VERSION 5.8 ;
BUSBITCHARS "[]" ;
DIVIDERCHAR "/" ;
UNITS
    DATABASE MICRONS 1000 ;
END UNITS

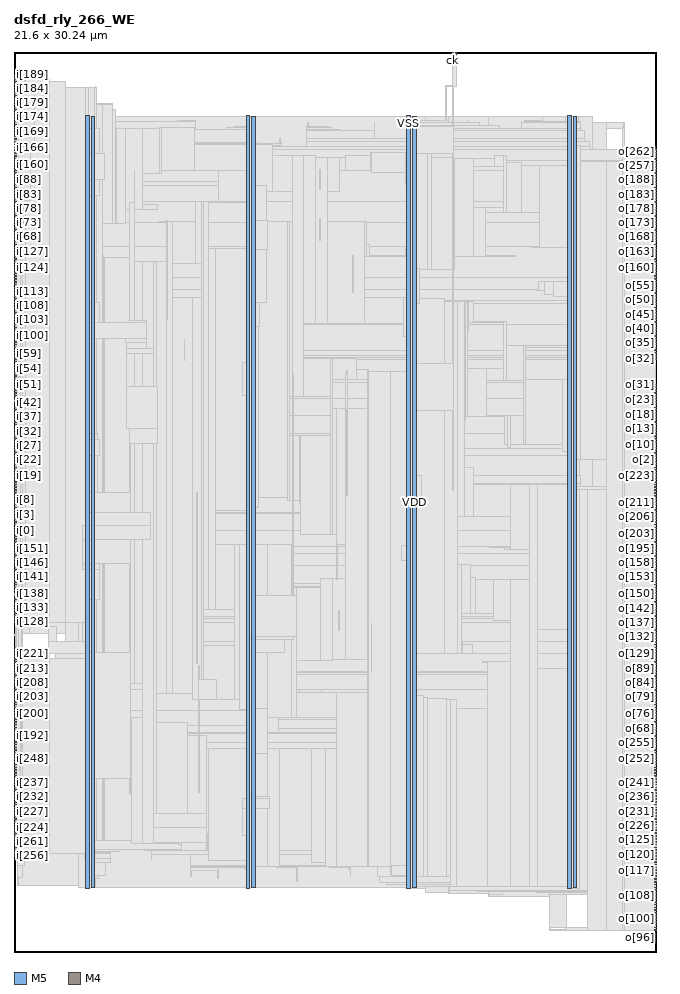
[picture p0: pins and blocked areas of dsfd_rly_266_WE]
MACRO dsfd_rly_266_WE
  FOREIGN dsfd_rly_266_WE 0 0 ;
  CLASS BLOCK ;
  SIZE 21.6 BY 30.24 ;
  PIN ck
    DIRECTION INPUT ;
    USE SIGNAL ;
    PORT
      LAYER M5 ;
        RECT  14.736 30.156 14.76 30.24 ;
    END
  END ck
  PIN i[0]
    DIRECTION INPUT ;
    USE SIGNAL ;
    PORT
      LAYER M4 ;
        RECT  0 14.16 0.084 14.184 ;
    END
  END i[0]
  PIN i[100]
    DIRECTION INPUT ;
    USE SIGNAL ;
    PORT
      LAYER M4 ;
        RECT  0 20.688 0.084 20.712 ;
    END
  END i[100]
  PIN i[101]
    DIRECTION INPUT ;
    USE SIGNAL ;
    PORT
      LAYER M4 ;
        RECT  0 20.784 0.084 20.808 ;
    END
  END i[101]
  PIN i[102]
    DIRECTION INPUT ;
    USE SIGNAL ;
    PORT
      LAYER M4 ;
        RECT  0 20.88 0.084 20.904 ;
    END
  END i[102]
  PIN i[103]
    DIRECTION INPUT ;
    USE SIGNAL ;
    PORT
      LAYER M4 ;
        RECT  0 20.976 0.084 21 ;
    END
  END i[103]
  PIN i[104]
    DIRECTION INPUT ;
    USE SIGNAL ;
    PORT
      LAYER M4 ;
        RECT  0 21.072 0.084 21.096 ;
    END
  END i[104]
  PIN i[105]
    DIRECTION INPUT ;
    USE SIGNAL ;
    PORT
      LAYER M4 ;
        RECT  0 21.168 0.084 21.192 ;
    END
  END i[105]
  PIN i[106]
    DIRECTION INPUT ;
    USE SIGNAL ;
    PORT
      LAYER M4 ;
        RECT  0 21.264 0.084 21.288 ;
    END
  END i[106]
  PIN i[107]
    DIRECTION INPUT ;
    USE SIGNAL ;
    PORT
      LAYER M4 ;
        RECT  0 21.36 0.084 21.384 ;
    END
  END i[107]
  PIN i[108]
    DIRECTION INPUT ;
    USE SIGNAL ;
    PORT
      LAYER M4 ;
        RECT  0 21.456 0.084 21.48 ;
    END
  END i[108]
  PIN i[109]
    DIRECTION INPUT ;
    USE SIGNAL ;
    PORT
      LAYER M4 ;
        RECT  0 21.552 0.084 21.576 ;
    END
  END i[109]
  PIN i[10]
    DIRECTION INPUT ;
    USE SIGNAL ;
    PORT
      LAYER M4 ;
        RECT  0 15.12 0.084 15.144 ;
    END
  END i[10]
  PIN i[110]
    DIRECTION INPUT ;
    USE SIGNAL ;
    PORT
      LAYER M4 ;
        RECT  0 21.648 0.084 21.672 ;
    END
  END i[110]
  PIN i[111]
    DIRECTION INPUT ;
    USE SIGNAL ;
    PORT
      LAYER M4 ;
        RECT  0 21.744 0.084 21.768 ;
    END
  END i[111]
  PIN i[112]
    DIRECTION INPUT ;
    USE SIGNAL ;
    PORT
      LAYER M4 ;
        RECT  0 21.84 0.084 21.864 ;
    END
  END i[112]
  PIN i[113]
    DIRECTION INPUT ;
    USE SIGNAL ;
    PORT
      LAYER M4 ;
        RECT  0 21.936 0.084 21.96 ;
    END
  END i[113]
  PIN i[114]
    DIRECTION INPUT ;
    USE SIGNAL ;
    PORT
      LAYER M4 ;
        RECT  0 22.032 0.084 22.056 ;
    END
  END i[114]
  PIN i[115]
    DIRECTION INPUT ;
    USE SIGNAL ;
    PORT
      LAYER M4 ;
        RECT  0 22.128 0.084 22.152 ;
    END
  END i[115]
  PIN i[116]
    DIRECTION INPUT ;
    USE SIGNAL ;
    PORT
      LAYER M4 ;
        RECT  0 22.224 0.084 22.248 ;
    END
  END i[116]
  PIN i[117]
    DIRECTION INPUT ;
    USE SIGNAL ;
    PORT
      LAYER M4 ;
        RECT  0 22.32 0.084 22.344 ;
    END
  END i[117]
  PIN i[118]
    DIRECTION INPUT ;
    USE SIGNAL ;
    PORT
      LAYER M4 ;
        RECT  0 22.416 0.084 22.44 ;
    END
  END i[118]
  PIN i[119]
    DIRECTION INPUT ;
    USE SIGNAL ;
    PORT
      LAYER M4 ;
        RECT  0 22.512 0.084 22.536 ;
    END
  END i[119]
  PIN i[11]
    DIRECTION INPUT ;
    USE SIGNAL ;
    PORT
      LAYER M4 ;
        RECT  0 15.216 0.084 15.24 ;
    END
  END i[11]
  PIN i[120]
    DIRECTION INPUT ;
    USE SIGNAL ;
    PORT
      LAYER M4 ;
        RECT  0 22.608 0.084 22.632 ;
    END
  END i[120]
  PIN i[121]
    DIRECTION INPUT ;
    USE SIGNAL ;
    PORT
      LAYER M4 ;
        RECT  0 22.704 0.084 22.728 ;
    END
  END i[121]
  PIN i[122]
    DIRECTION INPUT ;
    USE SIGNAL ;
    PORT
      LAYER M4 ;
        RECT  0 22.8 0.084 22.824 ;
    END
  END i[122]
  PIN i[123]
    DIRECTION INPUT ;
    USE SIGNAL ;
    PORT
      LAYER M4 ;
        RECT  0 22.896 0.084 22.92 ;
    END
  END i[123]
  PIN i[124]
    DIRECTION INPUT ;
    USE SIGNAL ;
    PORT
      LAYER M4 ;
        RECT  0 22.992 0.084 23.016 ;
    END
  END i[124]
  PIN i[125]
    DIRECTION INPUT ;
    USE SIGNAL ;
    PORT
      LAYER M4 ;
        RECT  0 23.088 0.084 23.112 ;
    END
  END i[125]
  PIN i[126]
    DIRECTION INPUT ;
    USE SIGNAL ;
    PORT
      LAYER M4 ;
        RECT  0 23.184 0.084 23.208 ;
    END
  END i[126]
  PIN i[127]
    DIRECTION INPUT ;
    USE SIGNAL ;
    PORT
      LAYER M4 ;
        RECT  0 23.28 0.084 23.304 ;
    END
  END i[127]
  PIN i[128]
    DIRECTION INPUT ;
    USE SIGNAL ;
    PORT
      LAYER M4 ;
        RECT  0 11.088 0.084 11.112 ;
    END
  END i[128]
  PIN i[129]
    DIRECTION INPUT ;
    USE SIGNAL ;
    PORT
      LAYER M4 ;
        RECT  0 11.184 0.084 11.208 ;
    END
  END i[129]
  PIN i[12]
    DIRECTION INPUT ;
    USE SIGNAL ;
    PORT
      LAYER M4 ;
        RECT  0 15.312 0.084 15.336 ;
    END
  END i[12]
  PIN i[130]
    DIRECTION INPUT ;
    USE SIGNAL ;
    PORT
      LAYER M4 ;
        RECT  0 11.28 0.084 11.304 ;
    END
  END i[130]
  PIN i[131]
    DIRECTION INPUT ;
    USE SIGNAL ;
    PORT
      LAYER M4 ;
        RECT  0 11.376 0.084 11.4 ;
    END
  END i[131]
  PIN i[132]
    DIRECTION INPUT ;
    USE SIGNAL ;
    PORT
      LAYER M4 ;
        RECT  0 11.472 0.084 11.496 ;
    END
  END i[132]
  PIN i[133]
    DIRECTION INPUT ;
    USE SIGNAL ;
    PORT
      LAYER M4 ;
        RECT  0 11.568 0.084 11.592 ;
    END
  END i[133]
  PIN i[134]
    DIRECTION INPUT ;
    USE SIGNAL ;
    PORT
      LAYER M4 ;
        RECT  0 11.664 0.084 11.688 ;
    END
  END i[134]
  PIN i[135]
    DIRECTION INPUT ;
    USE SIGNAL ;
    PORT
      LAYER M4 ;
        RECT  0 11.76 0.084 11.784 ;
    END
  END i[135]
  PIN i[136]
    DIRECTION INPUT ;
    USE SIGNAL ;
    PORT
      LAYER M4 ;
        RECT  0 11.856 0.084 11.88 ;
    END
  END i[136]
  PIN i[137]
    DIRECTION INPUT ;
    USE SIGNAL ;
    PORT
      LAYER M4 ;
        RECT  0 11.952 0.084 11.976 ;
    END
  END i[137]
  PIN i[138]
    DIRECTION INPUT ;
    USE SIGNAL ;
    PORT
      LAYER M4 ;
        RECT  0 12.048 0.084 12.072 ;
    END
  END i[138]
  PIN i[139]
    DIRECTION INPUT ;
    USE SIGNAL ;
    PORT
      LAYER M4 ;
        RECT  0 12.144 0.084 12.168 ;
    END
  END i[139]
  PIN i[13]
    DIRECTION INPUT ;
    USE SIGNAL ;
    PORT
      LAYER M4 ;
        RECT  0 15.408 0.084 15.432 ;
    END
  END i[13]
  PIN i[140]
    DIRECTION INPUT ;
    USE SIGNAL ;
    PORT
      LAYER M4 ;
        RECT  0 12.24 0.084 12.264 ;
    END
  END i[140]
  PIN i[141]
    DIRECTION INPUT ;
    USE SIGNAL ;
    PORT
      LAYER M4 ;
        RECT  0 12.336 0.084 12.36 ;
    END
  END i[141]
  PIN i[142]
    DIRECTION INPUT ;
    USE SIGNAL ;
    PORT
      LAYER M4 ;
        RECT  0 12.432 0.084 12.456 ;
    END
  END i[142]
  PIN i[143]
    DIRECTION INPUT ;
    USE SIGNAL ;
    PORT
      LAYER M4 ;
        RECT  0 12.528 0.084 12.552 ;
    END
  END i[143]
  PIN i[144]
    DIRECTION INPUT ;
    USE SIGNAL ;
    PORT
      LAYER M4 ;
        RECT  0 12.624 0.084 12.648 ;
    END
  END i[144]
  PIN i[145]
    DIRECTION INPUT ;
    USE SIGNAL ;
    PORT
      LAYER M4 ;
        RECT  0 12.72 0.084 12.744 ;
    END
  END i[145]
  PIN i[146]
    DIRECTION INPUT ;
    USE SIGNAL ;
    PORT
      LAYER M4 ;
        RECT  0 12.816 0.084 12.84 ;
    END
  END i[146]
  PIN i[147]
    DIRECTION INPUT ;
    USE SIGNAL ;
    PORT
      LAYER M4 ;
        RECT  0 12.912 0.084 12.936 ;
    END
  END i[147]
  PIN i[148]
    DIRECTION INPUT ;
    USE SIGNAL ;
    PORT
      LAYER M4 ;
        RECT  0 13.008 0.084 13.032 ;
    END
  END i[148]
  PIN i[149]
    DIRECTION INPUT ;
    USE SIGNAL ;
    PORT
      LAYER M4 ;
        RECT  0 13.104 0.084 13.128 ;
    END
  END i[149]
  PIN i[14]
    DIRECTION INPUT ;
    USE SIGNAL ;
    PORT
      LAYER M4 ;
        RECT  0 15.504 0.084 15.528 ;
    END
  END i[14]
  PIN i[150]
    DIRECTION INPUT ;
    USE SIGNAL ;
    PORT
      LAYER M4 ;
        RECT  0 13.2 0.084 13.224 ;
    END
  END i[150]
  PIN i[151]
    DIRECTION INPUT ;
    USE SIGNAL ;
    PORT
      LAYER M4 ;
        RECT  0 13.296 0.084 13.32 ;
    END
  END i[151]
  PIN i[152]
    DIRECTION INPUT ;
    USE SIGNAL ;
    PORT
      LAYER M4 ;
        RECT  0 13.392 0.084 13.416 ;
    END
  END i[152]
  PIN i[153]
    DIRECTION INPUT ;
    USE SIGNAL ;
    PORT
      LAYER M4 ;
        RECT  0 13.488 0.084 13.512 ;
    END
  END i[153]
  PIN i[154]
    DIRECTION INPUT ;
    USE SIGNAL ;
    PORT
      LAYER M4 ;
        RECT  0 13.584 0.084 13.608 ;
    END
  END i[154]
  PIN i[155]
    DIRECTION INPUT ;
    USE SIGNAL ;
    PORT
      LAYER M4 ;
        RECT  0 13.68 0.084 13.704 ;
    END
  END i[155]
  PIN i[156]
    DIRECTION INPUT ;
    USE SIGNAL ;
    PORT
      LAYER M4 ;
        RECT  0 13.776 0.084 13.8 ;
    END
  END i[156]
  PIN i[157]
    DIRECTION INPUT ;
    USE SIGNAL ;
    PORT
      LAYER M4 ;
        RECT  0 13.872 0.084 13.896 ;
    END
  END i[157]
  PIN i[158]
    DIRECTION INPUT ;
    USE SIGNAL ;
    PORT
      LAYER M4 ;
        RECT  0 13.968 0.084 13.992 ;
    END
  END i[158]
  PIN i[159]
    DIRECTION INPUT ;
    USE SIGNAL ;
    PORT
      LAYER M4 ;
        RECT  0 14.064 0.084 14.088 ;
    END
  END i[159]
  PIN i[15]
    DIRECTION INPUT ;
    USE SIGNAL ;
    PORT
      LAYER M4 ;
        RECT  0 15.6 0.084 15.624 ;
    END
  END i[15]
  PIN i[160]
    DIRECTION INPUT ;
    USE SIGNAL ;
    PORT
      LAYER M4 ;
        RECT  0 26.448 0.084 26.472 ;
    END
  END i[160]
  PIN i[161]
    DIRECTION INPUT ;
    USE SIGNAL ;
    PORT
      LAYER M4 ;
        RECT  0 26.544 0.084 26.568 ;
    END
  END i[161]
  PIN i[162]
    DIRECTION INPUT ;
    USE SIGNAL ;
    PORT
      LAYER M4 ;
        RECT  0 26.64 0.084 26.664 ;
    END
  END i[162]
  PIN i[163]
    DIRECTION INPUT ;
    USE SIGNAL ;
    PORT
      LAYER M4 ;
        RECT  0 26.736 0.084 26.76 ;
    END
  END i[163]
  PIN i[164]
    DIRECTION INPUT ;
    USE SIGNAL ;
    PORT
      LAYER M4 ;
        RECT  0 26.832 0.084 26.856 ;
    END
  END i[164]
  PIN i[165]
    DIRECTION INPUT ;
    USE SIGNAL ;
    PORT
      LAYER M4 ;
        RECT  0 26.928 0.084 26.952 ;
    END
  END i[165]
  PIN i[166]
    DIRECTION INPUT ;
    USE SIGNAL ;
    PORT
      LAYER M4 ;
        RECT  0 27.024 0.084 27.048 ;
    END
  END i[166]
  PIN i[167]
    DIRECTION INPUT ;
    USE SIGNAL ;
    PORT
      LAYER M4 ;
        RECT  0 27.12 0.084 27.144 ;
    END
  END i[167]
  PIN i[168]
    DIRECTION INPUT ;
    USE SIGNAL ;
    PORT
      LAYER M4 ;
        RECT  0 27.216 0.084 27.24 ;
    END
  END i[168]
  PIN i[169]
    DIRECTION INPUT ;
    USE SIGNAL ;
    PORT
      LAYER M4 ;
        RECT  0 27.312 0.084 27.336 ;
    END
  END i[169]
  PIN i[16]
    DIRECTION INPUT ;
    USE SIGNAL ;
    PORT
      LAYER M4 ;
        RECT  0 15.696 0.084 15.72 ;
    END
  END i[16]
  PIN i[170]
    DIRECTION INPUT ;
    USE SIGNAL ;
    PORT
      LAYER M4 ;
        RECT  0 27.408 0.084 27.432 ;
    END
  END i[170]
  PIN i[171]
    DIRECTION INPUT ;
    USE SIGNAL ;
    PORT
      LAYER M4 ;
        RECT  0 27.504 0.084 27.528 ;
    END
  END i[171]
  PIN i[172]
    DIRECTION INPUT ;
    USE SIGNAL ;
    PORT
      LAYER M4 ;
        RECT  0 27.6 0.084 27.624 ;
    END
  END i[172]
  PIN i[173]
    DIRECTION INPUT ;
    USE SIGNAL ;
    PORT
      LAYER M4 ;
        RECT  0 27.696 0.084 27.72 ;
    END
  END i[173]
  PIN i[174]
    DIRECTION INPUT ;
    USE SIGNAL ;
    PORT
      LAYER M4 ;
        RECT  0 27.792 0.084 27.816 ;
    END
  END i[174]
  PIN i[175]
    DIRECTION INPUT ;
    USE SIGNAL ;
    PORT
      LAYER M4 ;
        RECT  0 27.888 0.084 27.912 ;
    END
  END i[175]
  PIN i[176]
    DIRECTION INPUT ;
    USE SIGNAL ;
    PORT
      LAYER M4 ;
        RECT  0 27.984 0.084 28.008 ;
    END
  END i[176]
  PIN i[177]
    DIRECTION INPUT ;
    USE SIGNAL ;
    PORT
      LAYER M4 ;
        RECT  0 28.08 0.084 28.104 ;
    END
  END i[177]
  PIN i[178]
    DIRECTION INPUT ;
    USE SIGNAL ;
    PORT
      LAYER M4 ;
        RECT  0 28.176 0.084 28.2 ;
    END
  END i[178]
  PIN i[179]
    DIRECTION INPUT ;
    USE SIGNAL ;
    PORT
      LAYER M4 ;
        RECT  0 28.272 0.084 28.296 ;
    END
  END i[179]
  PIN i[17]
    DIRECTION INPUT ;
    USE SIGNAL ;
    PORT
      LAYER M4 ;
        RECT  0 15.792 0.084 15.816 ;
    END
  END i[17]
  PIN i[180]
    DIRECTION INPUT ;
    USE SIGNAL ;
    PORT
      LAYER M4 ;
        RECT  0 28.368 0.084 28.392 ;
    END
  END i[180]
  PIN i[181]
    DIRECTION INPUT ;
    USE SIGNAL ;
    PORT
      LAYER M4 ;
        RECT  0 28.464 0.084 28.488 ;
    END
  END i[181]
  PIN i[182]
    DIRECTION INPUT ;
    USE SIGNAL ;
    PORT
      LAYER M4 ;
        RECT  0 28.56 0.084 28.584 ;
    END
  END i[182]
  PIN i[183]
    DIRECTION INPUT ;
    USE SIGNAL ;
    PORT
      LAYER M4 ;
        RECT  0 28.656 0.084 28.68 ;
    END
  END i[183]
  PIN i[184]
    DIRECTION INPUT ;
    USE SIGNAL ;
    PORT
      LAYER M4 ;
        RECT  0 28.752 0.084 28.776 ;
    END
  END i[184]
  PIN i[185]
    DIRECTION INPUT ;
    USE SIGNAL ;
    PORT
      LAYER M4 ;
        RECT  0 28.848 0.084 28.872 ;
    END
  END i[185]
  PIN i[186]
    DIRECTION INPUT ;
    USE SIGNAL ;
    PORT
      LAYER M4 ;
        RECT  0 28.944 0.084 28.968 ;
    END
  END i[186]
  PIN i[187]
    DIRECTION INPUT ;
    USE SIGNAL ;
    PORT
      LAYER M4 ;
        RECT  0 29.04 0.084 29.064 ;
    END
  END i[187]
  PIN i[188]
    DIRECTION INPUT ;
    USE SIGNAL ;
    PORT
      LAYER M4 ;
        RECT  0 29.136 0.084 29.16 ;
    END
  END i[188]
  PIN i[189]
    DIRECTION INPUT ;
    USE SIGNAL ;
    PORT
      LAYER M4 ;
        RECT  0 29.232 0.084 29.256 ;
    END
  END i[189]
  PIN i[18]
    DIRECTION INPUT ;
    USE SIGNAL ;
    PORT
      LAYER M4 ;
        RECT  0 15.888 0.084 15.912 ;
    END
  END i[18]
  PIN i[190]
    DIRECTION INPUT ;
    USE SIGNAL ;
    PORT
      LAYER M4 ;
        RECT  0 29.328 0.084 29.352 ;
    END
  END i[190]
  PIN i[191]
    DIRECTION INPUT ;
    USE SIGNAL ;
    PORT
      LAYER M4 ;
        RECT  0 29.424 0.084 29.448 ;
    END
  END i[191]
  PIN i[192]
    DIRECTION INPUT ;
    USE SIGNAL ;
    PORT
      LAYER M4 ;
        RECT  0 7.248 0.084 7.272 ;
    END
  END i[192]
  PIN i[193]
    DIRECTION INPUT ;
    USE SIGNAL ;
    PORT
      LAYER M4 ;
        RECT  0 7.344 0.084 7.368 ;
    END
  END i[193]
  PIN i[194]
    DIRECTION INPUT ;
    USE SIGNAL ;
    PORT
      LAYER M4 ;
        RECT  0 7.44 0.084 7.464 ;
    END
  END i[194]
  PIN i[195]
    DIRECTION INPUT ;
    USE SIGNAL ;
    PORT
      LAYER M4 ;
        RECT  0 7.536 0.084 7.56 ;
    END
  END i[195]
  PIN i[196]
    DIRECTION INPUT ;
    USE SIGNAL ;
    PORT
      LAYER M4 ;
        RECT  0 7.632 0.084 7.656 ;
    END
  END i[196]
  PIN i[197]
    DIRECTION INPUT ;
    USE SIGNAL ;
    PORT
      LAYER M4 ;
        RECT  0 7.728 0.084 7.752 ;
    END
  END i[197]
  PIN i[198]
    DIRECTION INPUT ;
    USE SIGNAL ;
    PORT
      LAYER M4 ;
        RECT  0 7.824 0.084 7.848 ;
    END
  END i[198]
  PIN i[199]
    DIRECTION INPUT ;
    USE SIGNAL ;
    PORT
      LAYER M4 ;
        RECT  0 7.92 0.084 7.944 ;
    END
  END i[199]
  PIN i[19]
    DIRECTION INPUT ;
    USE SIGNAL ;
    PORT
      LAYER M4 ;
        RECT  0 15.984 0.084 16.008 ;
    END
  END i[19]
  PIN i[1]
    DIRECTION INPUT ;
    USE SIGNAL ;
    PORT
      LAYER M4 ;
        RECT  0 14.256 0.084 14.28 ;
    END
  END i[1]
  PIN i[200]
    DIRECTION INPUT ;
    USE SIGNAL ;
    PORT
      LAYER M4 ;
        RECT  0 8.016 0.084 8.04 ;
    END
  END i[200]
  PIN i[201]
    DIRECTION INPUT ;
    USE SIGNAL ;
    PORT
      LAYER M4 ;
        RECT  0 8.112 0.084 8.136 ;
    END
  END i[201]
  PIN i[202]
    DIRECTION INPUT ;
    USE SIGNAL ;
    PORT
      LAYER M4 ;
        RECT  0 8.208 0.084 8.232 ;
    END
  END i[202]
  PIN i[203]
    DIRECTION INPUT ;
    USE SIGNAL ;
    PORT
      LAYER M4 ;
        RECT  0 8.304 0.084 8.328 ;
    END
  END i[203]
  PIN i[204]
    DIRECTION INPUT ;
    USE SIGNAL ;
    PORT
      LAYER M4 ;
        RECT  0 8.4 0.084 8.424 ;
    END
  END i[204]
  PIN i[205]
    DIRECTION INPUT ;
    USE SIGNAL ;
    PORT
      LAYER M4 ;
        RECT  0 8.496 0.084 8.52 ;
    END
  END i[205]
  PIN i[206]
    DIRECTION INPUT ;
    USE SIGNAL ;
    PORT
      LAYER M4 ;
        RECT  0 8.592 0.084 8.616 ;
    END
  END i[206]
  PIN i[207]
    DIRECTION INPUT ;
    USE SIGNAL ;
    PORT
      LAYER M4 ;
        RECT  0 8.688 0.084 8.712 ;
    END
  END i[207]
  PIN i[208]
    DIRECTION INPUT ;
    USE SIGNAL ;
    PORT
      LAYER M4 ;
        RECT  0 8.784 0.084 8.808 ;
    END
  END i[208]
  PIN i[209]
    DIRECTION INPUT ;
    USE SIGNAL ;
    PORT
      LAYER M4 ;
        RECT  0 8.88 0.084 8.904 ;
    END
  END i[209]
  PIN i[20]
    DIRECTION INPUT ;
    USE SIGNAL ;
    PORT
      LAYER M4 ;
        RECT  0 16.08 0.084 16.104 ;
    END
  END i[20]
  PIN i[210]
    DIRECTION INPUT ;
    USE SIGNAL ;
    PORT
      LAYER M4 ;
        RECT  0 8.976 0.084 9 ;
    END
  END i[210]
  PIN i[211]
    DIRECTION INPUT ;
    USE SIGNAL ;
    PORT
      LAYER M4 ;
        RECT  0 9.072 0.084 9.096 ;
    END
  END i[211]
  PIN i[212]
    DIRECTION INPUT ;
    USE SIGNAL ;
    PORT
      LAYER M4 ;
        RECT  0 9.168 0.084 9.192 ;
    END
  END i[212]
  PIN i[213]
    DIRECTION INPUT ;
    USE SIGNAL ;
    PORT
      LAYER M4 ;
        RECT  0 9.264 0.084 9.288 ;
    END
  END i[213]
  PIN i[214]
    DIRECTION INPUT ;
    USE SIGNAL ;
    PORT
      LAYER M4 ;
        RECT  0 9.36 0.084 9.384 ;
    END
  END i[214]
  PIN i[215]
    DIRECTION INPUT ;
    USE SIGNAL ;
    PORT
      LAYER M4 ;
        RECT  0 9.456 0.084 9.48 ;
    END
  END i[215]
  PIN i[216]
    DIRECTION INPUT ;
    USE SIGNAL ;
    PORT
      LAYER M4 ;
        RECT  0 9.552 0.084 9.576 ;
    END
  END i[216]
  PIN i[217]
    DIRECTION INPUT ;
    USE SIGNAL ;
    PORT
      LAYER M4 ;
        RECT  0 9.648 0.084 9.672 ;
    END
  END i[217]
  PIN i[218]
    DIRECTION INPUT ;
    USE SIGNAL ;
    PORT
      LAYER M4 ;
        RECT  0 9.744 0.084 9.768 ;
    END
  END i[218]
  PIN i[219]
    DIRECTION INPUT ;
    USE SIGNAL ;
    PORT
      LAYER M4 ;
        RECT  0 9.84 0.084 9.864 ;
    END
  END i[219]
  PIN i[21]
    DIRECTION INPUT ;
    USE SIGNAL ;
    PORT
      LAYER M4 ;
        RECT  0 16.176 0.084 16.2 ;
    END
  END i[21]
  PIN i[220]
    DIRECTION INPUT ;
    USE SIGNAL ;
    PORT
      LAYER M4 ;
        RECT  0 9.936 0.084 9.96 ;
    END
  END i[220]
  PIN i[221]
    DIRECTION INPUT ;
    USE SIGNAL ;
    PORT
      LAYER M4 ;
        RECT  0 10.032 0.084 10.056 ;
    END
  END i[221]
  PIN i[222]
    DIRECTION INPUT ;
    USE SIGNAL ;
    PORT
      LAYER M4 ;
        RECT  0 10.128 0.084 10.152 ;
    END
  END i[222]
  PIN i[223]
    DIRECTION INPUT ;
    USE SIGNAL ;
    PORT
      LAYER M4 ;
        RECT  0 10.224 0.084 10.248 ;
    END
  END i[223]
  PIN i[224]
    DIRECTION INPUT ;
    USE SIGNAL ;
    PORT
      LAYER M4 ;
        RECT  0 4.176 0.084 4.2 ;
    END
  END i[224]
  PIN i[225]
    DIRECTION INPUT ;
    USE SIGNAL ;
    PORT
      LAYER M4 ;
        RECT  0 4.272 0.084 4.296 ;
    END
  END i[225]
  PIN i[226]
    DIRECTION INPUT ;
    USE SIGNAL ;
    PORT
      LAYER M4 ;
        RECT  0 4.368 0.084 4.392 ;
    END
  END i[226]
  PIN i[227]
    DIRECTION INPUT ;
    USE SIGNAL ;
    PORT
      LAYER M4 ;
        RECT  0 4.464 0.084 4.488 ;
    END
  END i[227]
  PIN i[228]
    DIRECTION INPUT ;
    USE SIGNAL ;
    PORT
      LAYER M4 ;
        RECT  0 4.56 0.084 4.584 ;
    END
  END i[228]
  PIN i[229]
    DIRECTION INPUT ;
    USE SIGNAL ;
    PORT
      LAYER M4 ;
        RECT  0 4.656 0.084 4.68 ;
    END
  END i[229]
  PIN i[22]
    DIRECTION INPUT ;
    USE SIGNAL ;
    PORT
      LAYER M4 ;
        RECT  0 16.272 0.084 16.296 ;
    END
  END i[22]
  PIN i[230]
    DIRECTION INPUT ;
    USE SIGNAL ;
    PORT
      LAYER M4 ;
        RECT  0 4.752 0.084 4.776 ;
    END
  END i[230]
  PIN i[231]
    DIRECTION INPUT ;
    USE SIGNAL ;
    PORT
      LAYER M4 ;
        RECT  0 4.848 0.084 4.872 ;
    END
  END i[231]
  PIN i[232]
    DIRECTION INPUT ;
    USE SIGNAL ;
    PORT
      LAYER M4 ;
        RECT  0 4.944 0.084 4.968 ;
    END
  END i[232]
  PIN i[233]
    DIRECTION INPUT ;
    USE SIGNAL ;
    PORT
      LAYER M4 ;
        RECT  0 5.04 0.084 5.064 ;
    END
  END i[233]
  PIN i[234]
    DIRECTION INPUT ;
    USE SIGNAL ;
    PORT
      LAYER M4 ;
        RECT  0 5.136 0.084 5.16 ;
    END
  END i[234]
  PIN i[235]
    DIRECTION INPUT ;
    USE SIGNAL ;
    PORT
      LAYER M4 ;
        RECT  0 5.232 0.084 5.256 ;
    END
  END i[235]
  PIN i[236]
    DIRECTION INPUT ;
    USE SIGNAL ;
    PORT
      LAYER M4 ;
        RECT  0 5.328 0.084 5.352 ;
    END
  END i[236]
  PIN i[237]
    DIRECTION INPUT ;
    USE SIGNAL ;
    PORT
      LAYER M4 ;
        RECT  0 5.424 0.084 5.448 ;
    END
  END i[237]
  PIN i[238]
    DIRECTION INPUT ;
    USE SIGNAL ;
    PORT
      LAYER M4 ;
        RECT  0 5.52 0.084 5.544 ;
    END
  END i[238]
  PIN i[239]
    DIRECTION INPUT ;
    USE SIGNAL ;
    PORT
      LAYER M4 ;
        RECT  0 5.616 0.084 5.64 ;
    END
  END i[239]
  PIN i[23]
    DIRECTION INPUT ;
    USE SIGNAL ;
    PORT
      LAYER M4 ;
        RECT  0 16.368 0.084 16.392 ;
    END
  END i[23]
  PIN i[240]
    DIRECTION INPUT ;
    USE SIGNAL ;
    PORT
      LAYER M4 ;
        RECT  0 5.712 0.084 5.736 ;
    END
  END i[240]
  PIN i[241]
    DIRECTION INPUT ;
    USE SIGNAL ;
    PORT
      LAYER M4 ;
        RECT  0 5.808 0.084 5.832 ;
    END
  END i[241]
  PIN i[242]
    DIRECTION INPUT ;
    USE SIGNAL ;
    PORT
      LAYER M4 ;
        RECT  0 5.904 0.084 5.928 ;
    END
  END i[242]
  PIN i[243]
    DIRECTION INPUT ;
    USE SIGNAL ;
    PORT
      LAYER M4 ;
        RECT  0 6 0.084 6.024 ;
    END
  END i[243]
  PIN i[244]
    DIRECTION INPUT ;
    USE SIGNAL ;
    PORT
      LAYER M4 ;
        RECT  0 6.096 0.084 6.12 ;
    END
  END i[244]
  PIN i[245]
    DIRECTION INPUT ;
    USE SIGNAL ;
    PORT
      LAYER M4 ;
        RECT  0 6.192 0.084 6.216 ;
    END
  END i[245]
  PIN i[246]
    DIRECTION INPUT ;
    USE SIGNAL ;
    PORT
      LAYER M4 ;
        RECT  0 6.288 0.084 6.312 ;
    END
  END i[246]
  PIN i[247]
    DIRECTION INPUT ;
    USE SIGNAL ;
    PORT
      LAYER M4 ;
        RECT  0 6.384 0.084 6.408 ;
    END
  END i[247]
  PIN i[248]
    DIRECTION INPUT ;
    USE SIGNAL ;
    PORT
      LAYER M4 ;
        RECT  0 6.48 0.084 6.504 ;
    END
  END i[248]
  PIN i[249]
    DIRECTION INPUT ;
    USE SIGNAL ;
    PORT
      LAYER M4 ;
        RECT  0 6.576 0.084 6.6 ;
    END
  END i[249]
  PIN i[24]
    DIRECTION INPUT ;
    USE SIGNAL ;
    PORT
      LAYER M4 ;
        RECT  0 16.464 0.084 16.488 ;
    END
  END i[24]
  PIN i[250]
    DIRECTION INPUT ;
    USE SIGNAL ;
    PORT
      LAYER M4 ;
        RECT  0 6.672 0.084 6.696 ;
    END
  END i[250]
  PIN i[251]
    DIRECTION INPUT ;
    USE SIGNAL ;
    PORT
      LAYER M4 ;
        RECT  0 6.768 0.084 6.792 ;
    END
  END i[251]
  PIN i[252]
    DIRECTION INPUT ;
    USE SIGNAL ;
    PORT
      LAYER M4 ;
        RECT  0 6.864 0.084 6.888 ;
    END
  END i[252]
  PIN i[253]
    DIRECTION INPUT ;
    USE SIGNAL ;
    PORT
      LAYER M4 ;
        RECT  0 6.96 0.084 6.984 ;
    END
  END i[253]
  PIN i[254]
    DIRECTION INPUT ;
    USE SIGNAL ;
    PORT
      LAYER M4 ;
        RECT  0 7.056 0.084 7.08 ;
    END
  END i[254]
  PIN i[255]
    DIRECTION INPUT ;
    USE SIGNAL ;
    PORT
      LAYER M4 ;
        RECT  0 7.152 0.084 7.176 ;
    END
  END i[255]
  PIN i[256]
    DIRECTION INPUT ;
    USE SIGNAL ;
    PORT
      LAYER M4 ;
        RECT  0 3.216 0.084 3.24 ;
    END
  END i[256]
  PIN i[257]
    DIRECTION INPUT ;
    USE SIGNAL ;
    PORT
      LAYER M4 ;
        RECT  0 3.312 0.084 3.336 ;
    END
  END i[257]
  PIN i[258]
    DIRECTION INPUT ;
    USE SIGNAL ;
    PORT
      LAYER M4 ;
        RECT  0 3.408 0.084 3.432 ;
    END
  END i[258]
  PIN i[259]
    DIRECTION INPUT ;
    USE SIGNAL ;
    PORT
      LAYER M4 ;
        RECT  0 3.504 0.084 3.528 ;
    END
  END i[259]
  PIN i[25]
    DIRECTION INPUT ;
    USE SIGNAL ;
    PORT
      LAYER M4 ;
        RECT  0 16.56 0.084 16.584 ;
    END
  END i[25]
  PIN i[260]
    DIRECTION INPUT ;
    USE SIGNAL ;
    PORT
      LAYER M4 ;
        RECT  0 3.6 0.084 3.624 ;
    END
  END i[260]
  PIN i[261]
    DIRECTION INPUT ;
    USE SIGNAL ;
    PORT
      LAYER M4 ;
        RECT  0 3.696 0.084 3.72 ;
    END
  END i[261]
  PIN i[262]
    DIRECTION INPUT ;
    USE SIGNAL ;
    PORT
      LAYER M4 ;
        RECT  0 3.792 0.084 3.816 ;
    END
  END i[262]
  PIN i[263]
    DIRECTION INPUT ;
    USE SIGNAL ;
    PORT
      LAYER M4 ;
        RECT  0 3.888 0.084 3.912 ;
    END
  END i[263]
  PIN i[264]
    DIRECTION INPUT ;
    USE SIGNAL ;
    PORT
      LAYER M4 ;
        RECT  0 3.984 0.084 4.008 ;
    END
  END i[264]
  PIN i[265]
    DIRECTION INPUT ;
    USE SIGNAL ;
    PORT
      LAYER M4 ;
        RECT  0 4.08 0.084 4.104 ;
    END
  END i[265]
  PIN i[26]
    DIRECTION INPUT ;
    USE SIGNAL ;
    PORT
      LAYER M4 ;
        RECT  0 16.656 0.084 16.68 ;
    END
  END i[26]
  PIN i[27]
    DIRECTION INPUT ;
    USE SIGNAL ;
    PORT
      LAYER M4 ;
        RECT  0 16.752 0.084 16.776 ;
    END
  END i[27]
  PIN i[28]
    DIRECTION INPUT ;
    USE SIGNAL ;
    PORT
      LAYER M4 ;
        RECT  0 16.848 0.084 16.872 ;
    END
  END i[28]
  PIN i[29]
    DIRECTION INPUT ;
    USE SIGNAL ;
    PORT
      LAYER M4 ;
        RECT  0 16.944 0.084 16.968 ;
    END
  END i[29]
  PIN i[2]
    DIRECTION INPUT ;
    USE SIGNAL ;
    PORT
      LAYER M4 ;
        RECT  0 14.352 0.084 14.376 ;
    END
  END i[2]
  PIN i[30]
    DIRECTION INPUT ;
    USE SIGNAL ;
    PORT
      LAYER M4 ;
        RECT  0 17.04 0.084 17.064 ;
    END
  END i[30]
  PIN i[31]
    DIRECTION INPUT ;
    USE SIGNAL ;
    PORT
      LAYER M4 ;
        RECT  0 17.136 0.084 17.16 ;
    END
  END i[31]
  PIN i[32]
    DIRECTION INPUT ;
    USE SIGNAL ;
    PORT
      LAYER M4 ;
        RECT  0 17.232 0.084 17.256 ;
    END
  END i[32]
  PIN i[33]
    DIRECTION INPUT ;
    USE SIGNAL ;
    PORT
      LAYER M4 ;
        RECT  0 17.328 0.084 17.352 ;
    END
  END i[33]
  PIN i[34]
    DIRECTION INPUT ;
    USE SIGNAL ;
    PORT
      LAYER M4 ;
        RECT  0 17.424 0.084 17.448 ;
    END
  END i[34]
  PIN i[35]
    DIRECTION INPUT ;
    USE SIGNAL ;
    PORT
      LAYER M4 ;
        RECT  0 17.52 0.084 17.544 ;
    END
  END i[35]
  PIN i[36]
    DIRECTION INPUT ;
    USE SIGNAL ;
    PORT
      LAYER M4 ;
        RECT  0 17.616 0.084 17.64 ;
    END
  END i[36]
  PIN i[37]
    DIRECTION INPUT ;
    USE SIGNAL ;
    PORT
      LAYER M4 ;
        RECT  0 17.712 0.084 17.736 ;
    END
  END i[37]
  PIN i[38]
    DIRECTION INPUT ;
    USE SIGNAL ;
    PORT
      LAYER M4 ;
        RECT  0 17.808 0.084 17.832 ;
    END
  END i[38]
  PIN i[39]
    DIRECTION INPUT ;
    USE SIGNAL ;
    PORT
      LAYER M4 ;
        RECT  0 17.904 0.084 17.928 ;
    END
  END i[39]
  PIN i[3]
    DIRECTION INPUT ;
    USE SIGNAL ;
    PORT
      LAYER M4 ;
        RECT  0 14.448 0.084 14.472 ;
    END
  END i[3]
  PIN i[40]
    DIRECTION INPUT ;
    USE SIGNAL ;
    PORT
      LAYER M4 ;
        RECT  0 18 0.084 18.024 ;
    END
  END i[40]
  PIN i[41]
    DIRECTION INPUT ;
    USE SIGNAL ;
    PORT
      LAYER M4 ;
        RECT  0 18.096 0.084 18.12 ;
    END
  END i[41]
  PIN i[42]
    DIRECTION INPUT ;
    USE SIGNAL ;
    PORT
      LAYER M4 ;
        RECT  0 18.192 0.084 18.216 ;
    END
  END i[42]
  PIN i[43]
    DIRECTION INPUT ;
    USE SIGNAL ;
    PORT
      LAYER M4 ;
        RECT  0 18.288 0.084 18.312 ;
    END
  END i[43]
  PIN i[44]
    DIRECTION INPUT ;
    USE SIGNAL ;
    PORT
      LAYER M4 ;
        RECT  0 18.384 0.084 18.408 ;
    END
  END i[44]
  PIN i[45]
    DIRECTION INPUT ;
    USE SIGNAL ;
    PORT
      LAYER M4 ;
        RECT  0 18.48 0.084 18.504 ;
    END
  END i[45]
  PIN i[46]
    DIRECTION INPUT ;
    USE SIGNAL ;
    PORT
      LAYER M4 ;
        RECT  0 18.576 0.084 18.6 ;
    END
  END i[46]
  PIN i[47]
    DIRECTION INPUT ;
    USE SIGNAL ;
    PORT
      LAYER M4 ;
        RECT  0 18.672 0.084 18.696 ;
    END
  END i[47]
  PIN i[48]
    DIRECTION INPUT ;
    USE SIGNAL ;
    PORT
      LAYER M4 ;
        RECT  0 18.768 0.084 18.792 ;
    END
  END i[48]
  PIN i[49]
    DIRECTION INPUT ;
    USE SIGNAL ;
    PORT
      LAYER M4 ;
        RECT  0 18.864 0.084 18.888 ;
    END
  END i[49]
  PIN i[4]
    DIRECTION INPUT ;
    USE SIGNAL ;
    PORT
      LAYER M4 ;
        RECT  0 14.544 0.084 14.568 ;
    END
  END i[4]
  PIN i[50]
    DIRECTION INPUT ;
    USE SIGNAL ;
    PORT
      LAYER M4 ;
        RECT  0 18.96 0.084 18.984 ;
    END
  END i[50]
  PIN i[51]
    DIRECTION INPUT ;
    USE SIGNAL ;
    PORT
      LAYER M4 ;
        RECT  0 19.056 0.084 19.08 ;
    END
  END i[51]
  PIN i[52]
    DIRECTION INPUT ;
    USE SIGNAL ;
    PORT
      LAYER M4 ;
        RECT  0 19.152 0.084 19.176 ;
    END
  END i[52]
  PIN i[53]
    DIRECTION INPUT ;
    USE SIGNAL ;
    PORT
      LAYER M4 ;
        RECT  0 19.248 0.084 19.272 ;
    END
  END i[53]
  PIN i[54]
    DIRECTION INPUT ;
    USE SIGNAL ;
    PORT
      LAYER M4 ;
        RECT  0 19.344 0.084 19.368 ;
    END
  END i[54]
  PIN i[55]
    DIRECTION INPUT ;
    USE SIGNAL ;
    PORT
      LAYER M4 ;
        RECT  0 19.44 0.084 19.464 ;
    END
  END i[55]
  PIN i[56]
    DIRECTION INPUT ;
    USE SIGNAL ;
    PORT
      LAYER M4 ;
        RECT  0 19.536 0.084 19.56 ;
    END
  END i[56]
  PIN i[57]
    DIRECTION INPUT ;
    USE SIGNAL ;
    PORT
      LAYER M4 ;
        RECT  0 19.632 0.084 19.656 ;
    END
  END i[57]
  PIN i[58]
    DIRECTION INPUT ;
    USE SIGNAL ;
    PORT
      LAYER M4 ;
        RECT  0 19.728 0.084 19.752 ;
    END
  END i[58]
  PIN i[59]
    DIRECTION INPUT ;
    USE SIGNAL ;
    PORT
      LAYER M4 ;
        RECT  0 19.824 0.084 19.848 ;
    END
  END i[59]
  PIN i[5]
    DIRECTION INPUT ;
    USE SIGNAL ;
    PORT
      LAYER M4 ;
        RECT  0 14.64 0.084 14.664 ;
    END
  END i[5]
  PIN i[60]
    DIRECTION INPUT ;
    USE SIGNAL ;
    PORT
      LAYER M4 ;
        RECT  0 19.92 0.084 19.944 ;
    END
  END i[60]
  PIN i[61]
    DIRECTION INPUT ;
    USE SIGNAL ;
    PORT
      LAYER M4 ;
        RECT  0 20.016 0.084 20.04 ;
    END
  END i[61]
  PIN i[62]
    DIRECTION INPUT ;
    USE SIGNAL ;
    PORT
      LAYER M4 ;
        RECT  0 20.112 0.084 20.136 ;
    END
  END i[62]
  PIN i[63]
    DIRECTION INPUT ;
    USE SIGNAL ;
    PORT
      LAYER M4 ;
        RECT  0 20.208 0.084 20.232 ;
    END
  END i[63]
  PIN i[64]
    DIRECTION INPUT ;
    USE SIGNAL ;
    PORT
      LAYER M4 ;
        RECT  0 23.376 0.084 23.4 ;
    END
  END i[64]
  PIN i[65]
    DIRECTION INPUT ;
    USE SIGNAL ;
    PORT
      LAYER M4 ;
        RECT  0 23.472 0.084 23.496 ;
    END
  END i[65]
  PIN i[66]
    DIRECTION INPUT ;
    USE SIGNAL ;
    PORT
      LAYER M4 ;
        RECT  0 23.568 0.084 23.592 ;
    END
  END i[66]
  PIN i[67]
    DIRECTION INPUT ;
    USE SIGNAL ;
    PORT
      LAYER M4 ;
        RECT  0 23.664 0.084 23.688 ;
    END
  END i[67]
  PIN i[68]
    DIRECTION INPUT ;
    USE SIGNAL ;
    PORT
      LAYER M4 ;
        RECT  0 23.76 0.084 23.784 ;
    END
  END i[68]
  PIN i[69]
    DIRECTION INPUT ;
    USE SIGNAL ;
    PORT
      LAYER M4 ;
        RECT  0 23.856 0.084 23.88 ;
    END
  END i[69]
  PIN i[6]
    DIRECTION INPUT ;
    USE SIGNAL ;
    PORT
      LAYER M4 ;
        RECT  0 14.736 0.084 14.76 ;
    END
  END i[6]
  PIN i[70]
    DIRECTION INPUT ;
    USE SIGNAL ;
    PORT
      LAYER M4 ;
        RECT  0 23.952 0.084 23.976 ;
    END
  END i[70]
  PIN i[71]
    DIRECTION INPUT ;
    USE SIGNAL ;
    PORT
      LAYER M4 ;
        RECT  0 24.048 0.084 24.072 ;
    END
  END i[71]
  PIN i[72]
    DIRECTION INPUT ;
    USE SIGNAL ;
    PORT
      LAYER M4 ;
        RECT  0 24.144 0.084 24.168 ;
    END
  END i[72]
  PIN i[73]
    DIRECTION INPUT ;
    USE SIGNAL ;
    PORT
      LAYER M4 ;
        RECT  0 24.24 0.084 24.264 ;
    END
  END i[73]
  PIN i[74]
    DIRECTION INPUT ;
    USE SIGNAL ;
    PORT
      LAYER M4 ;
        RECT  0 24.336 0.084 24.36 ;
    END
  END i[74]
  PIN i[75]
    DIRECTION INPUT ;
    USE SIGNAL ;
    PORT
      LAYER M4 ;
        RECT  0 24.432 0.084 24.456 ;
    END
  END i[75]
  PIN i[76]
    DIRECTION INPUT ;
    USE SIGNAL ;
    PORT
      LAYER M4 ;
        RECT  0 24.528 0.084 24.552 ;
    END
  END i[76]
  PIN i[77]
    DIRECTION INPUT ;
    USE SIGNAL ;
    PORT
      LAYER M4 ;
        RECT  0 24.624 0.084 24.648 ;
    END
  END i[77]
  PIN i[78]
    DIRECTION INPUT ;
    USE SIGNAL ;
    PORT
      LAYER M4 ;
        RECT  0 24.72 0.084 24.744 ;
    END
  END i[78]
  PIN i[79]
    DIRECTION INPUT ;
    USE SIGNAL ;
    PORT
      LAYER M4 ;
        RECT  0 24.816 0.084 24.84 ;
    END
  END i[79]
  PIN i[7]
    DIRECTION INPUT ;
    USE SIGNAL ;
    PORT
      LAYER M4 ;
        RECT  0 14.832 0.084 14.856 ;
    END
  END i[7]
  PIN i[80]
    DIRECTION INPUT ;
    USE SIGNAL ;
    PORT
      LAYER M4 ;
        RECT  0 24.912 0.084 24.936 ;
    END
  END i[80]
  PIN i[81]
    DIRECTION INPUT ;
    USE SIGNAL ;
    PORT
      LAYER M4 ;
        RECT  0 25.008 0.084 25.032 ;
    END
  END i[81]
  PIN i[82]
    DIRECTION INPUT ;
    USE SIGNAL ;
    PORT
      LAYER M4 ;
        RECT  0 25.104 0.084 25.128 ;
    END
  END i[82]
  PIN i[83]
    DIRECTION INPUT ;
    USE SIGNAL ;
    PORT
      LAYER M4 ;
        RECT  0 25.2 0.084 25.224 ;
    END
  END i[83]
  PIN i[84]
    DIRECTION INPUT ;
    USE SIGNAL ;
    PORT
      LAYER M4 ;
        RECT  0 25.296 0.084 25.32 ;
    END
  END i[84]
  PIN i[85]
    DIRECTION INPUT ;
    USE SIGNAL ;
    PORT
      LAYER M4 ;
        RECT  0 25.392 0.084 25.416 ;
    END
  END i[85]
  PIN i[86]
    DIRECTION INPUT ;
    USE SIGNAL ;
    PORT
      LAYER M4 ;
        RECT  0 25.488 0.084 25.512 ;
    END
  END i[86]
  PIN i[87]
    DIRECTION INPUT ;
    USE SIGNAL ;
    PORT
      LAYER M4 ;
        RECT  0 25.584 0.084 25.608 ;
    END
  END i[87]
  PIN i[88]
    DIRECTION INPUT ;
    USE SIGNAL ;
    PORT
      LAYER M4 ;
        RECT  0 25.68 0.084 25.704 ;
    END
  END i[88]
  PIN i[89]
    DIRECTION INPUT ;
    USE SIGNAL ;
    PORT
      LAYER M4 ;
        RECT  0 25.776 0.084 25.8 ;
    END
  END i[89]
  PIN i[8]
    DIRECTION INPUT ;
    USE SIGNAL ;
    PORT
      LAYER M4 ;
        RECT  0 14.928 0.084 14.952 ;
    END
  END i[8]
  PIN i[90]
    DIRECTION INPUT ;
    USE SIGNAL ;
    PORT
      LAYER M4 ;
        RECT  0 25.872 0.084 25.896 ;
    END
  END i[90]
  PIN i[91]
    DIRECTION INPUT ;
    USE SIGNAL ;
    PORT
      LAYER M4 ;
        RECT  0 25.968 0.084 25.992 ;
    END
  END i[91]
  PIN i[92]
    DIRECTION INPUT ;
    USE SIGNAL ;
    PORT
      LAYER M4 ;
        RECT  0 26.064 0.084 26.088 ;
    END
  END i[92]
  PIN i[93]
    DIRECTION INPUT ;
    USE SIGNAL ;
    PORT
      LAYER M4 ;
        RECT  0 26.16 0.084 26.184 ;
    END
  END i[93]
  PIN i[94]
    DIRECTION INPUT ;
    USE SIGNAL ;
    PORT
      LAYER M4 ;
        RECT  0 26.256 0.084 26.28 ;
    END
  END i[94]
  PIN i[95]
    DIRECTION INPUT ;
    USE SIGNAL ;
    PORT
      LAYER M4 ;
        RECT  0 26.352 0.084 26.376 ;
    END
  END i[95]
  PIN i[96]
    DIRECTION INPUT ;
    USE SIGNAL ;
    PORT
      LAYER M4 ;
        RECT  0 20.304 0.084 20.328 ;
    END
  END i[96]
  PIN i[97]
    DIRECTION INPUT ;
    USE SIGNAL ;
    PORT
      LAYER M4 ;
        RECT  0 20.4 0.084 20.424 ;
    END
  END i[97]
  PIN i[98]
    DIRECTION INPUT ;
    USE SIGNAL ;
    PORT
      LAYER M4 ;
        RECT  0 20.496 0.084 20.52 ;
    END
  END i[98]
  PIN i[99]
    DIRECTION INPUT ;
    USE SIGNAL ;
    PORT
      LAYER M4 ;
        RECT  0 20.592 0.084 20.616 ;
    END
  END i[99]
  PIN i[9]
    DIRECTION INPUT ;
    USE SIGNAL ;
    PORT
      LAYER M4 ;
        RECT  0 15.024 0.084 15.048 ;
    END
  END i[9]
  PIN o[0]
    DIRECTION OUTPUT ;
    USE SIGNAL ;
    PORT
      LAYER M4 ;
        RECT  21.516 16.08 21.6 16.104 ;
    END
  END o[0]
  PIN o[100]
    DIRECTION OUTPUT ;
    USE SIGNAL ;
    PORT
      LAYER M4 ;
        RECT  21.516 1.104 21.6 1.128 ;
    END
  END o[100]
  PIN o[101]
    DIRECTION OUTPUT ;
    USE SIGNAL ;
    PORT
      LAYER M4 ;
        RECT  21.516 1.2 21.6 1.224 ;
    END
  END o[101]
  PIN o[102]
    DIRECTION OUTPUT ;
    USE SIGNAL ;
    PORT
      LAYER M4 ;
        RECT  21.516 1.296 21.6 1.32 ;
    END
  END o[102]
  PIN o[103]
    DIRECTION OUTPUT ;
    USE SIGNAL ;
    PORT
      LAYER M4 ;
        RECT  21.516 1.392 21.6 1.416 ;
    END
  END o[103]
  PIN o[104]
    DIRECTION OUTPUT ;
    USE SIGNAL ;
    PORT
      LAYER M4 ;
        RECT  21.516 1.488 21.6 1.512 ;
    END
  END o[104]
  PIN o[105]
    DIRECTION OUTPUT ;
    USE SIGNAL ;
    PORT
      LAYER M4 ;
        RECT  21.516 1.584 21.6 1.608 ;
    END
  END o[105]
  PIN o[106]
    DIRECTION OUTPUT ;
    USE SIGNAL ;
    PORT
      LAYER M4 ;
        RECT  21.516 1.68 21.6 1.704 ;
    END
  END o[106]
  PIN o[107]
    DIRECTION OUTPUT ;
    USE SIGNAL ;
    PORT
      LAYER M4 ;
        RECT  21.516 1.776 21.6 1.8 ;
    END
  END o[107]
  PIN o[108]
    DIRECTION OUTPUT ;
    USE SIGNAL ;
    PORT
      LAYER M4 ;
        RECT  21.516 1.872 21.6 1.896 ;
    END
  END o[108]
  PIN o[109]
    DIRECTION OUTPUT ;
    USE SIGNAL ;
    PORT
      LAYER M4 ;
        RECT  21.516 1.968 21.6 1.992 ;
    END
  END o[109]
  PIN o[10]
    DIRECTION OUTPUT ;
    USE SIGNAL ;
    PORT
      LAYER M4 ;
        RECT  21.516 17.04 21.6 17.064 ;
    END
  END o[10]
  PIN o[110]
    DIRECTION OUTPUT ;
    USE SIGNAL ;
    PORT
      LAYER M4 ;
        RECT  21.516 2.064 21.6 2.088 ;
    END
  END o[110]
  PIN o[111]
    DIRECTION OUTPUT ;
    USE SIGNAL ;
    PORT
      LAYER M4 ;
        RECT  21.516 2.16 21.6 2.184 ;
    END
  END o[111]
  PIN o[112]
    DIRECTION OUTPUT ;
    USE SIGNAL ;
    PORT
      LAYER M4 ;
        RECT  21.516 2.256 21.6 2.28 ;
    END
  END o[112]
  PIN o[113]
    DIRECTION OUTPUT ;
    USE SIGNAL ;
    PORT
      LAYER M4 ;
        RECT  21.516 2.352 21.6 2.376 ;
    END
  END o[113]
  PIN o[114]
    DIRECTION OUTPUT ;
    USE SIGNAL ;
    PORT
      LAYER M4 ;
        RECT  21.516 2.448 21.6 2.472 ;
    END
  END o[114]
  PIN o[115]
    DIRECTION OUTPUT ;
    USE SIGNAL ;
    PORT
      LAYER M4 ;
        RECT  21.516 2.544 21.6 2.568 ;
    END
  END o[115]
  PIN o[116]
    DIRECTION OUTPUT ;
    USE SIGNAL ;
    PORT
      LAYER M4 ;
        RECT  21.516 2.64 21.6 2.664 ;
    END
  END o[116]
  PIN o[117]
    DIRECTION OUTPUT ;
    USE SIGNAL ;
    PORT
      LAYER M4 ;
        RECT  21.516 2.736 21.6 2.76 ;
    END
  END o[117]
  PIN o[118]
    DIRECTION OUTPUT ;
    USE SIGNAL ;
    PORT
      LAYER M4 ;
        RECT  21.516 2.832 21.6 2.856 ;
    END
  END o[118]
  PIN o[119]
    DIRECTION OUTPUT ;
    USE SIGNAL ;
    PORT
      LAYER M4 ;
        RECT  21.516 2.928 21.6 2.952 ;
    END
  END o[119]
  PIN o[11]
    DIRECTION OUTPUT ;
    USE SIGNAL ;
    PORT
      LAYER M4 ;
        RECT  21.516 17.136 21.6 17.16 ;
    END
  END o[11]
  PIN o[120]
    DIRECTION OUTPUT ;
    USE SIGNAL ;
    PORT
      LAYER M4 ;
        RECT  21.516 3.024 21.6 3.048 ;
    END
  END o[120]
  PIN o[121]
    DIRECTION OUTPUT ;
    USE SIGNAL ;
    PORT
      LAYER M4 ;
        RECT  21.516 3.12 21.6 3.144 ;
    END
  END o[121]
  PIN o[122]
    DIRECTION OUTPUT ;
    USE SIGNAL ;
    PORT
      LAYER M4 ;
        RECT  21.516 3.216 21.6 3.24 ;
    END
  END o[122]
  PIN o[123]
    DIRECTION OUTPUT ;
    USE SIGNAL ;
    PORT
      LAYER M4 ;
        RECT  21.516 3.312 21.6 3.336 ;
    END
  END o[123]
  PIN o[124]
    DIRECTION OUTPUT ;
    USE SIGNAL ;
    PORT
      LAYER M4 ;
        RECT  21.516 3.408 21.6 3.432 ;
    END
  END o[124]
  PIN o[125]
    DIRECTION OUTPUT ;
    USE SIGNAL ;
    PORT
      LAYER M4 ;
        RECT  21.516 3.504 21.6 3.528 ;
    END
  END o[125]
  PIN o[126]
    DIRECTION OUTPUT ;
    USE SIGNAL ;
    PORT
      LAYER M4 ;
        RECT  21.516 3.6 21.6 3.624 ;
    END
  END o[126]
  PIN o[127]
    DIRECTION OUTPUT ;
    USE SIGNAL ;
    PORT
      LAYER M4 ;
        RECT  21.516 3.696 21.6 3.72 ;
    END
  END o[127]
  PIN o[128]
    DIRECTION OUTPUT ;
    USE SIGNAL ;
    PORT
      LAYER M4 ;
        RECT  21.516 9.936 21.6 9.96 ;
    END
  END o[128]
  PIN o[129]
    DIRECTION OUTPUT ;
    USE SIGNAL ;
    PORT
      LAYER M4 ;
        RECT  21.516 10.032 21.6 10.056 ;
    END
  END o[129]
  PIN o[12]
    DIRECTION OUTPUT ;
    USE SIGNAL ;
    PORT
      LAYER M4 ;
        RECT  21.516 17.232 21.6 17.256 ;
    END
  END o[12]
  PIN o[130]
    DIRECTION OUTPUT ;
    USE SIGNAL ;
    PORT
      LAYER M4 ;
        RECT  21.516 10.128 21.6 10.152 ;
    END
  END o[130]
  PIN o[131]
    DIRECTION OUTPUT ;
    USE SIGNAL ;
    PORT
      LAYER M4 ;
        RECT  21.516 10.224 21.6 10.248 ;
    END
  END o[131]
  PIN o[132]
    DIRECTION OUTPUT ;
    USE SIGNAL ;
    PORT
      LAYER M4 ;
        RECT  21.516 10.32 21.6 10.344 ;
    END
  END o[132]
  PIN o[133]
    DIRECTION OUTPUT ;
    USE SIGNAL ;
    PORT
      LAYER M4 ;
        RECT  21.516 10.416 21.6 10.44 ;
    END
  END o[133]
  PIN o[134]
    DIRECTION OUTPUT ;
    USE SIGNAL ;
    PORT
      LAYER M4 ;
        RECT  21.516 10.512 21.6 10.536 ;
    END
  END o[134]
  PIN o[135]
    DIRECTION OUTPUT ;
    USE SIGNAL ;
    PORT
      LAYER M4 ;
        RECT  21.516 10.608 21.6 10.632 ;
    END
  END o[135]
  PIN o[136]
    DIRECTION OUTPUT ;
    USE SIGNAL ;
    PORT
      LAYER M4 ;
        RECT  21.516 10.704 21.6 10.728 ;
    END
  END o[136]
  PIN o[137]
    DIRECTION OUTPUT ;
    USE SIGNAL ;
    PORT
      LAYER M4 ;
        RECT  21.516 10.8 21.6 10.824 ;
    END
  END o[137]
  PIN o[138]
    DIRECTION OUTPUT ;
    USE SIGNAL ;
    PORT
      LAYER M4 ;
        RECT  21.516 10.896 21.6 10.92 ;
    END
  END o[138]
  PIN o[139]
    DIRECTION OUTPUT ;
    USE SIGNAL ;
    PORT
      LAYER M4 ;
        RECT  21.516 10.992 21.6 11.016 ;
    END
  END o[139]
  PIN o[13]
    DIRECTION OUTPUT ;
    USE SIGNAL ;
    PORT
      LAYER M4 ;
        RECT  21.516 17.328 21.6 17.352 ;
    END
  END o[13]
  PIN o[140]
    DIRECTION OUTPUT ;
    USE SIGNAL ;
    PORT
      LAYER M4 ;
        RECT  21.516 11.088 21.6 11.112 ;
    END
  END o[140]
  PIN o[141]
    DIRECTION OUTPUT ;
    USE SIGNAL ;
    PORT
      LAYER M4 ;
        RECT  21.516 11.184 21.6 11.208 ;
    END
  END o[141]
  PIN o[142]
    DIRECTION OUTPUT ;
    USE SIGNAL ;
    PORT
      LAYER M4 ;
        RECT  21.516 11.28 21.6 11.304 ;
    END
  END o[142]
  PIN o[143]
    DIRECTION OUTPUT ;
    USE SIGNAL ;
    PORT
      LAYER M4 ;
        RECT  21.516 11.376 21.6 11.4 ;
    END
  END o[143]
  PIN o[144]
    DIRECTION OUTPUT ;
    USE SIGNAL ;
    PORT
      LAYER M4 ;
        RECT  21.516 11.472 21.6 11.496 ;
    END
  END o[144]
  PIN o[145]
    DIRECTION OUTPUT ;
    USE SIGNAL ;
    PORT
      LAYER M4 ;
        RECT  21.516 11.568 21.6 11.592 ;
    END
  END o[145]
  PIN o[146]
    DIRECTION OUTPUT ;
    USE SIGNAL ;
    PORT
      LAYER M4 ;
        RECT  21.516 11.664 21.6 11.688 ;
    END
  END o[146]
  PIN o[147]
    DIRECTION OUTPUT ;
    USE SIGNAL ;
    PORT
      LAYER M4 ;
        RECT  21.516 11.76 21.6 11.784 ;
    END
  END o[147]
  PIN o[148]
    DIRECTION OUTPUT ;
    USE SIGNAL ;
    PORT
      LAYER M4 ;
        RECT  21.516 11.856 21.6 11.88 ;
    END
  END o[148]
  PIN o[149]
    DIRECTION OUTPUT ;
    USE SIGNAL ;
    PORT
      LAYER M4 ;
        RECT  21.516 11.952 21.6 11.976 ;
    END
  END o[149]
  PIN o[14]
    DIRECTION OUTPUT ;
    USE SIGNAL ;
    PORT
      LAYER M4 ;
        RECT  21.516 17.424 21.6 17.448 ;
    END
  END o[14]
  PIN o[150]
    DIRECTION OUTPUT ;
    USE SIGNAL ;
    PORT
      LAYER M4 ;
        RECT  21.516 12.048 21.6 12.072 ;
    END
  END o[150]
  PIN o[151]
    DIRECTION OUTPUT ;
    USE SIGNAL ;
    PORT
      LAYER M4 ;
        RECT  21.516 12.144 21.6 12.168 ;
    END
  END o[151]
  PIN o[152]
    DIRECTION OUTPUT ;
    USE SIGNAL ;
    PORT
      LAYER M4 ;
        RECT  21.516 12.24 21.6 12.264 ;
    END
  END o[152]
  PIN o[153]
    DIRECTION OUTPUT ;
    USE SIGNAL ;
    PORT
      LAYER M4 ;
        RECT  21.516 12.336 21.6 12.36 ;
    END
  END o[153]
  PIN o[154]
    DIRECTION OUTPUT ;
    USE SIGNAL ;
    PORT
      LAYER M4 ;
        RECT  21.516 12.432 21.6 12.456 ;
    END
  END o[154]
  PIN o[155]
    DIRECTION OUTPUT ;
    USE SIGNAL ;
    PORT
      LAYER M4 ;
        RECT  21.516 12.528 21.6 12.552 ;
    END
  END o[155]
  PIN o[156]
    DIRECTION OUTPUT ;
    USE SIGNAL ;
    PORT
      LAYER M4 ;
        RECT  21.516 12.624 21.6 12.648 ;
    END
  END o[156]
  PIN o[157]
    DIRECTION OUTPUT ;
    USE SIGNAL ;
    PORT
      LAYER M4 ;
        RECT  21.516 12.72 21.6 12.744 ;
    END
  END o[157]
  PIN o[158]
    DIRECTION OUTPUT ;
    USE SIGNAL ;
    PORT
      LAYER M4 ;
        RECT  21.516 12.816 21.6 12.84 ;
    END
  END o[158]
  PIN o[159]
    DIRECTION OUTPUT ;
    USE SIGNAL ;
    PORT
      LAYER M4 ;
        RECT  21.516 12.912 21.6 12.936 ;
    END
  END o[159]
  PIN o[15]
    DIRECTION OUTPUT ;
    USE SIGNAL ;
    PORT
      LAYER M4 ;
        RECT  21.516 17.52 21.6 17.544 ;
    END
  END o[15]
  PIN o[160]
    DIRECTION OUTPUT ;
    USE SIGNAL ;
    PORT
      LAYER M4 ;
        RECT  21.516 22.992 21.6 23.016 ;
    END
  END o[160]
  PIN o[161]
    DIRECTION OUTPUT ;
    USE SIGNAL ;
    PORT
      LAYER M4 ;
        RECT  21.516 23.088 21.6 23.112 ;
    END
  END o[161]
  PIN o[162]
    DIRECTION OUTPUT ;
    USE SIGNAL ;
    PORT
      LAYER M4 ;
        RECT  21.516 23.184 21.6 23.208 ;
    END
  END o[162]
  PIN o[163]
    DIRECTION OUTPUT ;
    USE SIGNAL ;
    PORT
      LAYER M4 ;
        RECT  21.516 23.28 21.6 23.304 ;
    END
  END o[163]
  PIN o[164]
    DIRECTION OUTPUT ;
    USE SIGNAL ;
    PORT
      LAYER M4 ;
        RECT  21.516 23.376 21.6 23.4 ;
    END
  END o[164]
  PIN o[165]
    DIRECTION OUTPUT ;
    USE SIGNAL ;
    PORT
      LAYER M4 ;
        RECT  21.516 23.472 21.6 23.496 ;
    END
  END o[165]
  PIN o[166]
    DIRECTION OUTPUT ;
    USE SIGNAL ;
    PORT
      LAYER M4 ;
        RECT  21.516 23.568 21.6 23.592 ;
    END
  END o[166]
  PIN o[167]
    DIRECTION OUTPUT ;
    USE SIGNAL ;
    PORT
      LAYER M4 ;
        RECT  21.516 23.664 21.6 23.688 ;
    END
  END o[167]
  PIN o[168]
    DIRECTION OUTPUT ;
    USE SIGNAL ;
    PORT
      LAYER M4 ;
        RECT  21.516 23.76 21.6 23.784 ;
    END
  END o[168]
  PIN o[169]
    DIRECTION OUTPUT ;
    USE SIGNAL ;
    PORT
      LAYER M4 ;
        RECT  21.516 23.856 21.6 23.88 ;
    END
  END o[169]
  PIN o[16]
    DIRECTION OUTPUT ;
    USE SIGNAL ;
    PORT
      LAYER M4 ;
        RECT  21.516 17.616 21.6 17.64 ;
    END
  END o[16]
  PIN o[170]
    DIRECTION OUTPUT ;
    USE SIGNAL ;
    PORT
      LAYER M4 ;
        RECT  21.516 23.952 21.6 23.976 ;
    END
  END o[170]
  PIN o[171]
    DIRECTION OUTPUT ;
    USE SIGNAL ;
    PORT
      LAYER M4 ;
        RECT  21.516 24.048 21.6 24.072 ;
    END
  END o[171]
  PIN o[172]
    DIRECTION OUTPUT ;
    USE SIGNAL ;
    PORT
      LAYER M4 ;
        RECT  21.516 24.144 21.6 24.168 ;
    END
  END o[172]
  PIN o[173]
    DIRECTION OUTPUT ;
    USE SIGNAL ;
    PORT
      LAYER M4 ;
        RECT  21.516 24.24 21.6 24.264 ;
    END
  END o[173]
  PIN o[174]
    DIRECTION OUTPUT ;
    USE SIGNAL ;
    PORT
      LAYER M4 ;
        RECT  21.516 24.336 21.6 24.36 ;
    END
  END o[174]
  PIN o[175]
    DIRECTION OUTPUT ;
    USE SIGNAL ;
    PORT
      LAYER M4 ;
        RECT  21.516 24.432 21.6 24.456 ;
    END
  END o[175]
  PIN o[176]
    DIRECTION OUTPUT ;
    USE SIGNAL ;
    PORT
      LAYER M4 ;
        RECT  21.516 24.528 21.6 24.552 ;
    END
  END o[176]
  PIN o[177]
    DIRECTION OUTPUT ;
    USE SIGNAL ;
    PORT
      LAYER M4 ;
        RECT  21.516 24.624 21.6 24.648 ;
    END
  END o[177]
  PIN o[178]
    DIRECTION OUTPUT ;
    USE SIGNAL ;
    PORT
      LAYER M4 ;
        RECT  21.516 24.72 21.6 24.744 ;
    END
  END o[178]
  PIN o[179]
    DIRECTION OUTPUT ;
    USE SIGNAL ;
    PORT
      LAYER M4 ;
        RECT  21.516 24.816 21.6 24.84 ;
    END
  END o[179]
  PIN o[17]
    DIRECTION OUTPUT ;
    USE SIGNAL ;
    PORT
      LAYER M4 ;
        RECT  21.516 17.712 21.6 17.736 ;
    END
  END o[17]
  PIN o[180]
    DIRECTION OUTPUT ;
    USE SIGNAL ;
    PORT
      LAYER M4 ;
        RECT  21.516 24.912 21.6 24.936 ;
    END
  END o[180]
  PIN o[181]
    DIRECTION OUTPUT ;
    USE SIGNAL ;
    PORT
      LAYER M4 ;
        RECT  21.516 25.008 21.6 25.032 ;
    END
  END o[181]
  PIN o[182]
    DIRECTION OUTPUT ;
    USE SIGNAL ;
    PORT
      LAYER M4 ;
        RECT  21.516 25.104 21.6 25.128 ;
    END
  END o[182]
  PIN o[183]
    DIRECTION OUTPUT ;
    USE SIGNAL ;
    PORT
      LAYER M4 ;
        RECT  21.516 25.2 21.6 25.224 ;
    END
  END o[183]
  PIN o[184]
    DIRECTION OUTPUT ;
    USE SIGNAL ;
    PORT
      LAYER M4 ;
        RECT  21.516 25.296 21.6 25.32 ;
    END
  END o[184]
  PIN o[185]
    DIRECTION OUTPUT ;
    USE SIGNAL ;
    PORT
      LAYER M4 ;
        RECT  21.516 25.392 21.6 25.416 ;
    END
  END o[185]
  PIN o[186]
    DIRECTION OUTPUT ;
    USE SIGNAL ;
    PORT
      LAYER M4 ;
        RECT  21.516 25.488 21.6 25.512 ;
    END
  END o[186]
  PIN o[187]
    DIRECTION OUTPUT ;
    USE SIGNAL ;
    PORT
      LAYER M4 ;
        RECT  21.516 25.584 21.6 25.608 ;
    END
  END o[187]
  PIN o[188]
    DIRECTION OUTPUT ;
    USE SIGNAL ;
    PORT
      LAYER M4 ;
        RECT  21.516 25.68 21.6 25.704 ;
    END
  END o[188]
  PIN o[189]
    DIRECTION OUTPUT ;
    USE SIGNAL ;
    PORT
      LAYER M4 ;
        RECT  21.516 25.776 21.6 25.8 ;
    END
  END o[189]
  PIN o[18]
    DIRECTION OUTPUT ;
    USE SIGNAL ;
    PORT
      LAYER M4 ;
        RECT  21.516 17.808 21.6 17.832 ;
    END
  END o[18]
  PIN o[190]
    DIRECTION OUTPUT ;
    USE SIGNAL ;
    PORT
      LAYER M4 ;
        RECT  21.516 25.872 21.6 25.896 ;
    END
  END o[190]
  PIN o[191]
    DIRECTION OUTPUT ;
    USE SIGNAL ;
    PORT
      LAYER M4 ;
        RECT  21.516 25.968 21.6 25.992 ;
    END
  END o[191]
  PIN o[192]
    DIRECTION OUTPUT ;
    USE SIGNAL ;
    PORT
      LAYER M4 ;
        RECT  21.516 13.008 21.6 13.032 ;
    END
  END o[192]
  PIN o[193]
    DIRECTION OUTPUT ;
    USE SIGNAL ;
    PORT
      LAYER M4 ;
        RECT  21.516 13.104 21.6 13.128 ;
    END
  END o[193]
  PIN o[194]
    DIRECTION OUTPUT ;
    USE SIGNAL ;
    PORT
      LAYER M4 ;
        RECT  21.516 13.2 21.6 13.224 ;
    END
  END o[194]
  PIN o[195]
    DIRECTION OUTPUT ;
    USE SIGNAL ;
    PORT
      LAYER M4 ;
        RECT  21.516 13.296 21.6 13.32 ;
    END
  END o[195]
  PIN o[196]
    DIRECTION OUTPUT ;
    USE SIGNAL ;
    PORT
      LAYER M4 ;
        RECT  21.516 13.392 21.6 13.416 ;
    END
  END o[196]
  PIN o[197]
    DIRECTION OUTPUT ;
    USE SIGNAL ;
    PORT
      LAYER M4 ;
        RECT  21.516 13.488 21.6 13.512 ;
    END
  END o[197]
  PIN o[198]
    DIRECTION OUTPUT ;
    USE SIGNAL ;
    PORT
      LAYER M4 ;
        RECT  21.516 13.584 21.6 13.608 ;
    END
  END o[198]
  PIN o[199]
    DIRECTION OUTPUT ;
    USE SIGNAL ;
    PORT
      LAYER M4 ;
        RECT  21.516 13.68 21.6 13.704 ;
    END
  END o[199]
  PIN o[19]
    DIRECTION OUTPUT ;
    USE SIGNAL ;
    PORT
      LAYER M4 ;
        RECT  21.516 17.904 21.6 17.928 ;
    END
  END o[19]
  PIN o[1]
    DIRECTION OUTPUT ;
    USE SIGNAL ;
    PORT
      LAYER M4 ;
        RECT  21.516 16.176 21.6 16.2 ;
    END
  END o[1]
  PIN o[200]
    DIRECTION OUTPUT ;
    USE SIGNAL ;
    PORT
      LAYER M4 ;
        RECT  21.516 13.776 21.6 13.8 ;
    END
  END o[200]
  PIN o[201]
    DIRECTION OUTPUT ;
    USE SIGNAL ;
    PORT
      LAYER M4 ;
        RECT  21.516 13.872 21.6 13.896 ;
    END
  END o[201]
  PIN o[202]
    DIRECTION OUTPUT ;
    USE SIGNAL ;
    PORT
      LAYER M4 ;
        RECT  21.516 13.968 21.6 13.992 ;
    END
  END o[202]
  PIN o[203]
    DIRECTION OUTPUT ;
    USE SIGNAL ;
    PORT
      LAYER M4 ;
        RECT  21.516 14.064 21.6 14.088 ;
    END
  END o[203]
  PIN o[204]
    DIRECTION OUTPUT ;
    USE SIGNAL ;
    PORT
      LAYER M4 ;
        RECT  21.516 14.16 21.6 14.184 ;
    END
  END o[204]
  PIN o[205]
    DIRECTION OUTPUT ;
    USE SIGNAL ;
    PORT
      LAYER M4 ;
        RECT  21.516 14.256 21.6 14.28 ;
    END
  END o[205]
  PIN o[206]
    DIRECTION OUTPUT ;
    USE SIGNAL ;
    PORT
      LAYER M4 ;
        RECT  21.516 14.352 21.6 14.376 ;
    END
  END o[206]
  PIN o[207]
    DIRECTION OUTPUT ;
    USE SIGNAL ;
    PORT
      LAYER M4 ;
        RECT  21.516 14.448 21.6 14.472 ;
    END
  END o[207]
  PIN o[208]
    DIRECTION OUTPUT ;
    USE SIGNAL ;
    PORT
      LAYER M4 ;
        RECT  21.516 14.544 21.6 14.568 ;
    END
  END o[208]
  PIN o[209]
    DIRECTION OUTPUT ;
    USE SIGNAL ;
    PORT
      LAYER M4 ;
        RECT  21.516 14.64 21.6 14.664 ;
    END
  END o[209]
  PIN o[20]
    DIRECTION OUTPUT ;
    USE SIGNAL ;
    PORT
      LAYER M4 ;
        RECT  21.516 18 21.6 18.024 ;
    END
  END o[20]
  PIN o[210]
    DIRECTION OUTPUT ;
    USE SIGNAL ;
    PORT
      LAYER M4 ;
        RECT  21.516 14.736 21.6 14.76 ;
    END
  END o[210]
  PIN o[211]
    DIRECTION OUTPUT ;
    USE SIGNAL ;
    PORT
      LAYER M4 ;
        RECT  21.516 14.832 21.6 14.856 ;
    END
  END o[211]
  PIN o[212]
    DIRECTION OUTPUT ;
    USE SIGNAL ;
    PORT
      LAYER M4 ;
        RECT  21.516 14.928 21.6 14.952 ;
    END
  END o[212]
  PIN o[213]
    DIRECTION OUTPUT ;
    USE SIGNAL ;
    PORT
      LAYER M4 ;
        RECT  21.516 15.024 21.6 15.048 ;
    END
  END o[213]
  PIN o[214]
    DIRECTION OUTPUT ;
    USE SIGNAL ;
    PORT
      LAYER M4 ;
        RECT  21.516 15.12 21.6 15.144 ;
    END
  END o[214]
  PIN o[215]
    DIRECTION OUTPUT ;
    USE SIGNAL ;
    PORT
      LAYER M4 ;
        RECT  21.516 15.216 21.6 15.24 ;
    END
  END o[215]
  PIN o[216]
    DIRECTION OUTPUT ;
    USE SIGNAL ;
    PORT
      LAYER M4 ;
        RECT  21.516 15.312 21.6 15.336 ;
    END
  END o[216]
  PIN o[217]
    DIRECTION OUTPUT ;
    USE SIGNAL ;
    PORT
      LAYER M4 ;
        RECT  21.516 15.408 21.6 15.432 ;
    END
  END o[217]
  PIN o[218]
    DIRECTION OUTPUT ;
    USE SIGNAL ;
    PORT
      LAYER M4 ;
        RECT  21.516 15.504 21.6 15.528 ;
    END
  END o[218]
  PIN o[219]
    DIRECTION OUTPUT ;
    USE SIGNAL ;
    PORT
      LAYER M4 ;
        RECT  21.516 15.6 21.6 15.624 ;
    END
  END o[219]
  PIN o[21]
    DIRECTION OUTPUT ;
    USE SIGNAL ;
    PORT
      LAYER M4 ;
        RECT  21.516 18.096 21.6 18.12 ;
    END
  END o[21]
  PIN o[220]
    DIRECTION OUTPUT ;
    USE SIGNAL ;
    PORT
      LAYER M4 ;
        RECT  21.516 15.696 21.6 15.72 ;
    END
  END o[220]
  PIN o[221]
    DIRECTION OUTPUT ;
    USE SIGNAL ;
    PORT
      LAYER M4 ;
        RECT  21.516 15.792 21.6 15.816 ;
    END
  END o[221]
  PIN o[222]
    DIRECTION OUTPUT ;
    USE SIGNAL ;
    PORT
      LAYER M4 ;
        RECT  21.516 15.888 21.6 15.912 ;
    END
  END o[222]
  PIN o[223]
    DIRECTION OUTPUT ;
    USE SIGNAL ;
    PORT
      LAYER M4 ;
        RECT  21.516 15.984 21.6 16.008 ;
    END
  END o[223]
  PIN o[224]
    DIRECTION OUTPUT ;
    USE SIGNAL ;
    PORT
      LAYER M4 ;
        RECT  21.516 3.792 21.6 3.816 ;
    END
  END o[224]
  PIN o[225]
    DIRECTION OUTPUT ;
    USE SIGNAL ;
    PORT
      LAYER M4 ;
        RECT  21.516 3.888 21.6 3.912 ;
    END
  END o[225]
  PIN o[226]
    DIRECTION OUTPUT ;
    USE SIGNAL ;
    PORT
      LAYER M4 ;
        RECT  21.516 3.984 21.6 4.008 ;
    END
  END o[226]
  PIN o[227]
    DIRECTION OUTPUT ;
    USE SIGNAL ;
    PORT
      LAYER M4 ;
        RECT  21.516 4.08 21.6 4.104 ;
    END
  END o[227]
  PIN o[228]
    DIRECTION OUTPUT ;
    USE SIGNAL ;
    PORT
      LAYER M4 ;
        RECT  21.516 4.176 21.6 4.2 ;
    END
  END o[228]
  PIN o[229]
    DIRECTION OUTPUT ;
    USE SIGNAL ;
    PORT
      LAYER M4 ;
        RECT  21.516 4.272 21.6 4.296 ;
    END
  END o[229]
  PIN o[22]
    DIRECTION OUTPUT ;
    USE SIGNAL ;
    PORT
      LAYER M4 ;
        RECT  21.516 18.192 21.6 18.216 ;
    END
  END o[22]
  PIN o[230]
    DIRECTION OUTPUT ;
    USE SIGNAL ;
    PORT
      LAYER M4 ;
        RECT  21.516 4.368 21.6 4.392 ;
    END
  END o[230]
  PIN o[231]
    DIRECTION OUTPUT ;
    USE SIGNAL ;
    PORT
      LAYER M4 ;
        RECT  21.516 4.464 21.6 4.488 ;
    END
  END o[231]
  PIN o[232]
    DIRECTION OUTPUT ;
    USE SIGNAL ;
    PORT
      LAYER M4 ;
        RECT  21.516 4.56 21.6 4.584 ;
    END
  END o[232]
  PIN o[233]
    DIRECTION OUTPUT ;
    USE SIGNAL ;
    PORT
      LAYER M4 ;
        RECT  21.516 4.656 21.6 4.68 ;
    END
  END o[233]
  PIN o[234]
    DIRECTION OUTPUT ;
    USE SIGNAL ;
    PORT
      LAYER M4 ;
        RECT  21.516 4.752 21.6 4.776 ;
    END
  END o[234]
  PIN o[235]
    DIRECTION OUTPUT ;
    USE SIGNAL ;
    PORT
      LAYER M4 ;
        RECT  21.516 4.848 21.6 4.872 ;
    END
  END o[235]
  PIN o[236]
    DIRECTION OUTPUT ;
    USE SIGNAL ;
    PORT
      LAYER M4 ;
        RECT  21.516 4.944 21.6 4.968 ;
    END
  END o[236]
  PIN o[237]
    DIRECTION OUTPUT ;
    USE SIGNAL ;
    PORT
      LAYER M4 ;
        RECT  21.516 5.04 21.6 5.064 ;
    END
  END o[237]
  PIN o[238]
    DIRECTION OUTPUT ;
    USE SIGNAL ;
    PORT
      LAYER M4 ;
        RECT  21.516 5.136 21.6 5.16 ;
    END
  END o[238]
  PIN o[239]
    DIRECTION OUTPUT ;
    USE SIGNAL ;
    PORT
      LAYER M4 ;
        RECT  21.516 5.232 21.6 5.256 ;
    END
  END o[239]
  PIN o[23]
    DIRECTION OUTPUT ;
    USE SIGNAL ;
    PORT
      LAYER M4 ;
        RECT  21.516 18.288 21.6 18.312 ;
    END
  END o[23]
  PIN o[240]
    DIRECTION OUTPUT ;
    USE SIGNAL ;
    PORT
      LAYER M4 ;
        RECT  21.516 5.328 21.6 5.352 ;
    END
  END o[240]
  PIN o[241]
    DIRECTION OUTPUT ;
    USE SIGNAL ;
    PORT
      LAYER M4 ;
        RECT  21.516 5.424 21.6 5.448 ;
    END
  END o[241]
  PIN o[242]
    DIRECTION OUTPUT ;
    USE SIGNAL ;
    PORT
      LAYER M4 ;
        RECT  21.516 5.52 21.6 5.544 ;
    END
  END o[242]
  PIN o[243]
    DIRECTION OUTPUT ;
    USE SIGNAL ;
    PORT
      LAYER M4 ;
        RECT  21.516 5.616 21.6 5.64 ;
    END
  END o[243]
  PIN o[244]
    DIRECTION OUTPUT ;
    USE SIGNAL ;
    PORT
      LAYER M4 ;
        RECT  21.516 5.712 21.6 5.736 ;
    END
  END o[244]
  PIN o[245]
    DIRECTION OUTPUT ;
    USE SIGNAL ;
    PORT
      LAYER M4 ;
        RECT  21.516 5.808 21.6 5.832 ;
    END
  END o[245]
  PIN o[246]
    DIRECTION OUTPUT ;
    USE SIGNAL ;
    PORT
      LAYER M4 ;
        RECT  21.516 5.904 21.6 5.928 ;
    END
  END o[246]
  PIN o[247]
    DIRECTION OUTPUT ;
    USE SIGNAL ;
    PORT
      LAYER M4 ;
        RECT  21.516 6 21.6 6.024 ;
    END
  END o[247]
  PIN o[248]
    DIRECTION OUTPUT ;
    USE SIGNAL ;
    PORT
      LAYER M4 ;
        RECT  21.516 6.096 21.6 6.12 ;
    END
  END o[248]
  PIN o[249]
    DIRECTION OUTPUT ;
    USE SIGNAL ;
    PORT
      LAYER M4 ;
        RECT  21.516 6.192 21.6 6.216 ;
    END
  END o[249]
  PIN o[24]
    DIRECTION OUTPUT ;
    USE SIGNAL ;
    PORT
      LAYER M4 ;
        RECT  21.516 18.384 21.6 18.408 ;
    END
  END o[24]
  PIN o[250]
    DIRECTION OUTPUT ;
    USE SIGNAL ;
    PORT
      LAYER M4 ;
        RECT  21.516 6.288 21.6 6.312 ;
    END
  END o[250]
  PIN o[251]
    DIRECTION OUTPUT ;
    USE SIGNAL ;
    PORT
      LAYER M4 ;
        RECT  21.516 6.384 21.6 6.408 ;
    END
  END o[251]
  PIN o[252]
    DIRECTION OUTPUT ;
    USE SIGNAL ;
    PORT
      LAYER M4 ;
        RECT  21.516 6.48 21.6 6.504 ;
    END
  END o[252]
  PIN o[253]
    DIRECTION OUTPUT ;
    USE SIGNAL ;
    PORT
      LAYER M4 ;
        RECT  21.516 6.576 21.6 6.6 ;
    END
  END o[253]
  PIN o[254]
    DIRECTION OUTPUT ;
    USE SIGNAL ;
    PORT
      LAYER M4 ;
        RECT  21.516 6.672 21.6 6.696 ;
    END
  END o[254]
  PIN o[255]
    DIRECTION OUTPUT ;
    USE SIGNAL ;
    PORT
      LAYER M4 ;
        RECT  21.516 6.768 21.6 6.792 ;
    END
  END o[255]
  PIN o[256]
    DIRECTION OUTPUT ;
    USE SIGNAL ;
    PORT
      LAYER M4 ;
        RECT  21.516 26.064 21.6 26.088 ;
    END
  END o[256]
  PIN o[257]
    DIRECTION OUTPUT ;
    USE SIGNAL ;
    PORT
      LAYER M4 ;
        RECT  21.516 26.16 21.6 26.184 ;
    END
  END o[257]
  PIN o[258]
    DIRECTION OUTPUT ;
    USE SIGNAL ;
    PORT
      LAYER M4 ;
        RECT  21.516 26.256 21.6 26.28 ;
    END
  END o[258]
  PIN o[259]
    DIRECTION OUTPUT ;
    USE SIGNAL ;
    PORT
      LAYER M4 ;
        RECT  21.516 26.352 21.6 26.376 ;
    END
  END o[259]
  PIN o[25]
    DIRECTION OUTPUT ;
    USE SIGNAL ;
    PORT
      LAYER M4 ;
        RECT  21.516 18.48 21.6 18.504 ;
    END
  END o[25]
  PIN o[260]
    DIRECTION OUTPUT ;
    USE SIGNAL ;
    PORT
      LAYER M4 ;
        RECT  21.516 26.448 21.6 26.472 ;
    END
  END o[260]
  PIN o[261]
    DIRECTION OUTPUT ;
    USE SIGNAL ;
    PORT
      LAYER M4 ;
        RECT  21.516 26.544 21.6 26.568 ;
    END
  END o[261]
  PIN o[262]
    DIRECTION OUTPUT ;
    USE SIGNAL ;
    PORT
      LAYER M4 ;
        RECT  21.516 26.64 21.6 26.664 ;
    END
  END o[262]
  PIN o[263]
    DIRECTION OUTPUT ;
    USE SIGNAL ;
    PORT
      LAYER M4 ;
        RECT  21.516 26.736 21.6 26.76 ;
    END
  END o[263]
  PIN o[264]
    DIRECTION OUTPUT ;
    USE SIGNAL ;
    PORT
      LAYER M4 ;
        RECT  21.516 26.832 21.6 26.856 ;
    END
  END o[264]
  PIN o[265]
    DIRECTION OUTPUT ;
    USE SIGNAL ;
    PORT
      LAYER M4 ;
        RECT  21.516 26.928 21.6 26.952 ;
    END
  END o[265]
  PIN o[26]
    DIRECTION OUTPUT ;
    USE SIGNAL ;
    PORT
      LAYER M4 ;
        RECT  21.516 18.576 21.6 18.6 ;
    END
  END o[26]
  PIN o[27]
    DIRECTION OUTPUT ;
    USE SIGNAL ;
    PORT
      LAYER M4 ;
        RECT  21.516 18.672 21.6 18.696 ;
    END
  END o[27]
  PIN o[28]
    DIRECTION OUTPUT ;
    USE SIGNAL ;
    PORT
      LAYER M4 ;
        RECT  21.516 18.768 21.6 18.792 ;
    END
  END o[28]
  PIN o[29]
    DIRECTION OUTPUT ;
    USE SIGNAL ;
    PORT
      LAYER M4 ;
        RECT  21.516 18.864 21.6 18.888 ;
    END
  END o[29]
  PIN o[2]
    DIRECTION OUTPUT ;
    USE SIGNAL ;
    PORT
      LAYER M4 ;
        RECT  21.516 16.272 21.6 16.296 ;
    END
  END o[2]
  PIN o[30]
    DIRECTION OUTPUT ;
    USE SIGNAL ;
    PORT
      LAYER M4 ;
        RECT  21.516 18.96 21.6 18.984 ;
    END
  END o[30]
  PIN o[31]
    DIRECTION OUTPUT ;
    USE SIGNAL ;
    PORT
      LAYER M4 ;
        RECT  21.516 19.056 21.6 19.08 ;
    END
  END o[31]
  PIN o[32]
    DIRECTION OUTPUT ;
    USE SIGNAL ;
    PORT
      LAYER M4 ;
        RECT  21.516 19.92 21.6 19.944 ;
    END
  END o[32]
  PIN o[33]
    DIRECTION OUTPUT ;
    USE SIGNAL ;
    PORT
      LAYER M4 ;
        RECT  21.516 20.016 21.6 20.04 ;
    END
  END o[33]
  PIN o[34]
    DIRECTION OUTPUT ;
    USE SIGNAL ;
    PORT
      LAYER M4 ;
        RECT  21.516 20.112 21.6 20.136 ;
    END
  END o[34]
  PIN o[35]
    DIRECTION OUTPUT ;
    USE SIGNAL ;
    PORT
      LAYER M4 ;
        RECT  21.516 20.208 21.6 20.232 ;
    END
  END o[35]
  PIN o[36]
    DIRECTION OUTPUT ;
    USE SIGNAL ;
    PORT
      LAYER M4 ;
        RECT  21.516 20.304 21.6 20.328 ;
    END
  END o[36]
  PIN o[37]
    DIRECTION OUTPUT ;
    USE SIGNAL ;
    PORT
      LAYER M4 ;
        RECT  21.516 20.4 21.6 20.424 ;
    END
  END o[37]
  PIN o[38]
    DIRECTION OUTPUT ;
    USE SIGNAL ;
    PORT
      LAYER M4 ;
        RECT  21.516 20.496 21.6 20.52 ;
    END
  END o[38]
  PIN o[39]
    DIRECTION OUTPUT ;
    USE SIGNAL ;
    PORT
      LAYER M4 ;
        RECT  21.516 20.592 21.6 20.616 ;
    END
  END o[39]
  PIN o[3]
    DIRECTION OUTPUT ;
    USE SIGNAL ;
    PORT
      LAYER M4 ;
        RECT  21.516 16.368 21.6 16.392 ;
    END
  END o[3]
  PIN o[40]
    DIRECTION OUTPUT ;
    USE SIGNAL ;
    PORT
      LAYER M4 ;
        RECT  21.516 20.688 21.6 20.712 ;
    END
  END o[40]
  PIN o[41]
    DIRECTION OUTPUT ;
    USE SIGNAL ;
    PORT
      LAYER M4 ;
        RECT  21.516 20.784 21.6 20.808 ;
    END
  END o[41]
  PIN o[42]
    DIRECTION OUTPUT ;
    USE SIGNAL ;
    PORT
      LAYER M4 ;
        RECT  21.516 20.88 21.6 20.904 ;
    END
  END o[42]
  PIN o[43]
    DIRECTION OUTPUT ;
    USE SIGNAL ;
    PORT
      LAYER M4 ;
        RECT  21.516 20.976 21.6 21 ;
    END
  END o[43]
  PIN o[44]
    DIRECTION OUTPUT ;
    USE SIGNAL ;
    PORT
      LAYER M4 ;
        RECT  21.516 21.072 21.6 21.096 ;
    END
  END o[44]
  PIN o[45]
    DIRECTION OUTPUT ;
    USE SIGNAL ;
    PORT
      LAYER M4 ;
        RECT  21.516 21.168 21.6 21.192 ;
    END
  END o[45]
  PIN o[46]
    DIRECTION OUTPUT ;
    USE SIGNAL ;
    PORT
      LAYER M4 ;
        RECT  21.516 21.264 21.6 21.288 ;
    END
  END o[46]
  PIN o[47]
    DIRECTION OUTPUT ;
    USE SIGNAL ;
    PORT
      LAYER M4 ;
        RECT  21.516 21.36 21.6 21.384 ;
    END
  END o[47]
  PIN o[48]
    DIRECTION OUTPUT ;
    USE SIGNAL ;
    PORT
      LAYER M4 ;
        RECT  21.516 21.456 21.6 21.48 ;
    END
  END o[48]
  PIN o[49]
    DIRECTION OUTPUT ;
    USE SIGNAL ;
    PORT
      LAYER M4 ;
        RECT  21.516 21.552 21.6 21.576 ;
    END
  END o[49]
  PIN o[4]
    DIRECTION OUTPUT ;
    USE SIGNAL ;
    PORT
      LAYER M4 ;
        RECT  21.516 16.464 21.6 16.488 ;
    END
  END o[4]
  PIN o[50]
    DIRECTION OUTPUT ;
    USE SIGNAL ;
    PORT
      LAYER M4 ;
        RECT  21.516 21.648 21.6 21.672 ;
    END
  END o[50]
  PIN o[51]
    DIRECTION OUTPUT ;
    USE SIGNAL ;
    PORT
      LAYER M4 ;
        RECT  21.516 21.744 21.6 21.768 ;
    END
  END o[51]
  PIN o[52]
    DIRECTION OUTPUT ;
    USE SIGNAL ;
    PORT
      LAYER M4 ;
        RECT  21.516 21.84 21.6 21.864 ;
    END
  END o[52]
  PIN o[53]
    DIRECTION OUTPUT ;
    USE SIGNAL ;
    PORT
      LAYER M4 ;
        RECT  21.516 21.936 21.6 21.96 ;
    END
  END o[53]
  PIN o[54]
    DIRECTION OUTPUT ;
    USE SIGNAL ;
    PORT
      LAYER M4 ;
        RECT  21.516 22.032 21.6 22.056 ;
    END
  END o[54]
  PIN o[55]
    DIRECTION OUTPUT ;
    USE SIGNAL ;
    PORT
      LAYER M4 ;
        RECT  21.516 22.128 21.6 22.152 ;
    END
  END o[55]
  PIN o[56]
    DIRECTION OUTPUT ;
    USE SIGNAL ;
    PORT
      LAYER M4 ;
        RECT  21.516 22.224 21.6 22.248 ;
    END
  END o[56]
  PIN o[57]
    DIRECTION OUTPUT ;
    USE SIGNAL ;
    PORT
      LAYER M4 ;
        RECT  21.516 22.32 21.6 22.344 ;
    END
  END o[57]
  PIN o[58]
    DIRECTION OUTPUT ;
    USE SIGNAL ;
    PORT
      LAYER M4 ;
        RECT  21.516 22.416 21.6 22.44 ;
    END
  END o[58]
  PIN o[59]
    DIRECTION OUTPUT ;
    USE SIGNAL ;
    PORT
      LAYER M4 ;
        RECT  21.516 22.512 21.6 22.536 ;
    END
  END o[59]
  PIN o[5]
    DIRECTION OUTPUT ;
    USE SIGNAL ;
    PORT
      LAYER M4 ;
        RECT  21.516 16.56 21.6 16.584 ;
    END
  END o[5]
  PIN o[60]
    DIRECTION OUTPUT ;
    USE SIGNAL ;
    PORT
      LAYER M4 ;
        RECT  21.516 22.608 21.6 22.632 ;
    END
  END o[60]
  PIN o[61]
    DIRECTION OUTPUT ;
    USE SIGNAL ;
    PORT
      LAYER M4 ;
        RECT  21.516 22.704 21.6 22.728 ;
    END
  END o[61]
  PIN o[62]
    DIRECTION OUTPUT ;
    USE SIGNAL ;
    PORT
      LAYER M4 ;
        RECT  21.516 22.8 21.6 22.824 ;
    END
  END o[62]
  PIN o[63]
    DIRECTION OUTPUT ;
    USE SIGNAL ;
    PORT
      LAYER M4 ;
        RECT  21.516 22.896 21.6 22.92 ;
    END
  END o[63]
  PIN o[64]
    DIRECTION OUTPUT ;
    USE SIGNAL ;
    PORT
      LAYER M4 ;
        RECT  21.516 6.864 21.6 6.888 ;
    END
  END o[64]
  PIN o[65]
    DIRECTION OUTPUT ;
    USE SIGNAL ;
    PORT
      LAYER M4 ;
        RECT  21.516 6.96 21.6 6.984 ;
    END
  END o[65]
  PIN o[66]
    DIRECTION OUTPUT ;
    USE SIGNAL ;
    PORT
      LAYER M4 ;
        RECT  21.516 7.056 21.6 7.08 ;
    END
  END o[66]
  PIN o[67]
    DIRECTION OUTPUT ;
    USE SIGNAL ;
    PORT
      LAYER M4 ;
        RECT  21.516 7.152 21.6 7.176 ;
    END
  END o[67]
  PIN o[68]
    DIRECTION OUTPUT ;
    USE SIGNAL ;
    PORT
      LAYER M4 ;
        RECT  21.516 7.248 21.6 7.272 ;
    END
  END o[68]
  PIN o[69]
    DIRECTION OUTPUT ;
    USE SIGNAL ;
    PORT
      LAYER M4 ;
        RECT  21.516 7.344 21.6 7.368 ;
    END
  END o[69]
  PIN o[6]
    DIRECTION OUTPUT ;
    USE SIGNAL ;
    PORT
      LAYER M4 ;
        RECT  21.516 16.656 21.6 16.68 ;
    END
  END o[6]
  PIN o[70]
    DIRECTION OUTPUT ;
    USE SIGNAL ;
    PORT
      LAYER M4 ;
        RECT  21.516 7.44 21.6 7.464 ;
    END
  END o[70]
  PIN o[71]
    DIRECTION OUTPUT ;
    USE SIGNAL ;
    PORT
      LAYER M4 ;
        RECT  21.516 7.536 21.6 7.56 ;
    END
  END o[71]
  PIN o[72]
    DIRECTION OUTPUT ;
    USE SIGNAL ;
    PORT
      LAYER M4 ;
        RECT  21.516 7.632 21.6 7.656 ;
    END
  END o[72]
  PIN o[73]
    DIRECTION OUTPUT ;
    USE SIGNAL ;
    PORT
      LAYER M4 ;
        RECT  21.516 7.728 21.6 7.752 ;
    END
  END o[73]
  PIN o[74]
    DIRECTION OUTPUT ;
    USE SIGNAL ;
    PORT
      LAYER M4 ;
        RECT  21.516 7.824 21.6 7.848 ;
    END
  END o[74]
  PIN o[75]
    DIRECTION OUTPUT ;
    USE SIGNAL ;
    PORT
      LAYER M4 ;
        RECT  21.516 7.92 21.6 7.944 ;
    END
  END o[75]
  PIN o[76]
    DIRECTION OUTPUT ;
    USE SIGNAL ;
    PORT
      LAYER M4 ;
        RECT  21.516 8.016 21.6 8.04 ;
    END
  END o[76]
  PIN o[77]
    DIRECTION OUTPUT ;
    USE SIGNAL ;
    PORT
      LAYER M4 ;
        RECT  21.516 8.112 21.6 8.136 ;
    END
  END o[77]
  PIN o[78]
    DIRECTION OUTPUT ;
    USE SIGNAL ;
    PORT
      LAYER M4 ;
        RECT  21.516 8.208 21.6 8.232 ;
    END
  END o[78]
  PIN o[79]
    DIRECTION OUTPUT ;
    USE SIGNAL ;
    PORT
      LAYER M4 ;
        RECT  21.516 8.304 21.6 8.328 ;
    END
  END o[79]
  PIN o[7]
    DIRECTION OUTPUT ;
    USE SIGNAL ;
    PORT
      LAYER M4 ;
        RECT  21.516 16.752 21.6 16.776 ;
    END
  END o[7]
  PIN o[80]
    DIRECTION OUTPUT ;
    USE SIGNAL ;
    PORT
      LAYER M4 ;
        RECT  21.516 8.4 21.6 8.424 ;
    END
  END o[80]
  PIN o[81]
    DIRECTION OUTPUT ;
    USE SIGNAL ;
    PORT
      LAYER M4 ;
        RECT  21.516 8.496 21.6 8.52 ;
    END
  END o[81]
  PIN o[82]
    DIRECTION OUTPUT ;
    USE SIGNAL ;
    PORT
      LAYER M4 ;
        RECT  21.516 8.592 21.6 8.616 ;
    END
  END o[82]
  PIN o[83]
    DIRECTION OUTPUT ;
    USE SIGNAL ;
    PORT
      LAYER M4 ;
        RECT  21.516 8.688 21.6 8.712 ;
    END
  END o[83]
  PIN o[84]
    DIRECTION OUTPUT ;
    USE SIGNAL ;
    PORT
      LAYER M4 ;
        RECT  21.516 8.784 21.6 8.808 ;
    END
  END o[84]
  PIN o[85]
    DIRECTION OUTPUT ;
    USE SIGNAL ;
    PORT
      LAYER M4 ;
        RECT  21.516 8.88 21.6 8.904 ;
    END
  END o[85]
  PIN o[86]
    DIRECTION OUTPUT ;
    USE SIGNAL ;
    PORT
      LAYER M4 ;
        RECT  21.516 8.976 21.6 9 ;
    END
  END o[86]
  PIN o[87]
    DIRECTION OUTPUT ;
    USE SIGNAL ;
    PORT
      LAYER M4 ;
        RECT  21.516 9.072 21.6 9.096 ;
    END
  END o[87]
  PIN o[88]
    DIRECTION OUTPUT ;
    USE SIGNAL ;
    PORT
      LAYER M4 ;
        RECT  21.516 9.168 21.6 9.192 ;
    END
  END o[88]
  PIN o[89]
    DIRECTION OUTPUT ;
    USE SIGNAL ;
    PORT
      LAYER M4 ;
        RECT  21.516 9.264 21.6 9.288 ;
    END
  END o[89]
  PIN o[8]
    DIRECTION OUTPUT ;
    USE SIGNAL ;
    PORT
      LAYER M4 ;
        RECT  21.516 16.848 21.6 16.872 ;
    END
  END o[8]
  PIN o[90]
    DIRECTION OUTPUT ;
    USE SIGNAL ;
    PORT
      LAYER M4 ;
        RECT  21.516 9.36 21.6 9.384 ;
    END
  END o[90]
  PIN o[91]
    DIRECTION OUTPUT ;
    USE SIGNAL ;
    PORT
      LAYER M4 ;
        RECT  21.516 9.456 21.6 9.48 ;
    END
  END o[91]
  PIN o[92]
    DIRECTION OUTPUT ;
    USE SIGNAL ;
    PORT
      LAYER M4 ;
        RECT  21.516 9.552 21.6 9.576 ;
    END
  END o[92]
  PIN o[93]
    DIRECTION OUTPUT ;
    USE SIGNAL ;
    PORT
      LAYER M4 ;
        RECT  21.516 9.648 21.6 9.672 ;
    END
  END o[93]
  PIN o[94]
    DIRECTION OUTPUT ;
    USE SIGNAL ;
    PORT
      LAYER M4 ;
        RECT  21.516 9.744 21.6 9.768 ;
    END
  END o[94]
  PIN o[95]
    DIRECTION OUTPUT ;
    USE SIGNAL ;
    PORT
      LAYER M4 ;
        RECT  21.516 9.84 21.6 9.864 ;
    END
  END o[95]
  PIN o[96]
    DIRECTION OUTPUT ;
    USE SIGNAL ;
    PORT
      LAYER M4 ;
        RECT  21.516 0.72 21.6 0.744 ;
    END
  END o[96]
  PIN o[97]
    DIRECTION OUTPUT ;
    USE SIGNAL ;
    PORT
      LAYER M4 ;
        RECT  21.516 0.816 21.6 0.84 ;
    END
  END o[97]
  PIN o[98]
    DIRECTION OUTPUT ;
    USE SIGNAL ;
    PORT
      LAYER M4 ;
        RECT  21.516 0.912 21.6 0.936 ;
    END
  END o[98]
  PIN o[99]
    DIRECTION OUTPUT ;
    USE SIGNAL ;
    PORT
      LAYER M4 ;
        RECT  21.516 1.008 21.6 1.032 ;
    END
  END o[99]
  PIN o[9]
    DIRECTION OUTPUT ;
    USE SIGNAL ;
    PORT
      LAYER M4 ;
        RECT  21.516 16.944 21.6 16.968 ;
    END
  END o[9]
  PIN rs
    DIRECTION INPUT ;
    USE SIGNAL ;
    PORT
      LAYER M5 ;
        RECT  14.832 30.156 14.856 30.24 ;
    END
  END rs
  PIN VDD
    DIRECTION INOUT ;
    USE POWER ;
    PORT
      LAYER M5 ;
        RECT  18.792 2.151 18.912 28.089 ;
        RECT  13.392 2.151 13.512 28.089 ;
        RECT  7.992 2.151 8.112 28.089 ;
        RECT  2.592 2.151 2.712 28.089 ;
    END
  END VDD
  PIN VSS
    DIRECTION INOUT ;
    USE GROUND ;
    PORT
      LAYER M5 ;
        RECT  18.6 2.137 18.72 28.103 ;
        RECT  13.2 2.137 13.32 28.103 ;
        RECT  7.8 2.137 7.92 28.103 ;
        RECT  2.4 2.137 2.52 28.103 ;
    END
  END VSS
  OBS
    LAYER RVTN ;
     RECT  2.16 2.16 19.44 2.295 ;
     RECT  2.16 2.565 19.44 2.835 ;
     RECT  2.16 3.105 19.44 3.375 ;
     RECT  2.16 3.645 19.44 3.915 ;
     RECT  2.16 4.185 19.44 4.455 ;
     RECT  2.16 4.725 19.44 4.995 ;
     RECT  2.16 5.265 19.44 5.535 ;
     RECT  2.16 5.805 19.44 6.075 ;
     RECT  2.16 6.345 19.44 6.615 ;
     RECT  2.16 6.885 19.44 7.155 ;
     RECT  2.16 7.425 19.44 7.695 ;
     RECT  2.16 7.965 19.44 8.235 ;
     RECT  2.16 8.505 19.44 8.775 ;
     RECT  2.16 9.045 19.44 9.315 ;
     RECT  2.16 9.585 19.44 9.855 ;
     RECT  2.16 10.125 19.44 10.395 ;
     RECT  2.16 10.665 19.44 10.935 ;
     RECT  2.16 11.205 19.44 11.475 ;
     RECT  2.16 11.745 19.44 12.015 ;
     RECT  2.16 12.285 19.44 12.555 ;
     RECT  2.16 12.825 19.44 13.095 ;
     RECT  2.16 13.365 19.44 13.635 ;
     RECT  2.16 13.905 19.44 14.175 ;
     RECT  2.16 14.445 19.44 14.715 ;
     RECT  2.16 14.985 19.44 15.255 ;
     RECT  2.16 15.525 19.44 15.795 ;
     RECT  2.16 16.065 19.44 16.335 ;
     RECT  2.16 16.605 19.44 16.875 ;
     RECT  2.16 17.145 19.44 17.415 ;
     RECT  2.16 17.685 19.44 17.955 ;
     RECT  2.16 18.225 19.44 18.495 ;
     RECT  2.16 18.765 19.44 19.035 ;
     RECT  2.16 19.305 19.44 19.575 ;
     RECT  2.16 19.845 19.44 20.115 ;
     RECT  2.16 20.385 19.44 20.655 ;
     RECT  2.16 20.925 19.44 21.195 ;
     RECT  2.16 21.465 19.44 21.735 ;
     RECT  2.16 22.005 19.44 22.275 ;
     RECT  2.16 22.545 19.44 22.815 ;
     RECT  2.16 23.085 19.44 23.355 ;
     RECT  2.16 23.625 19.44 23.895 ;
     RECT  2.16 24.165 19.44 24.435 ;
     RECT  2.16 24.705 19.44 24.975 ;
     RECT  2.16 25.245 19.44 25.515 ;
     RECT  2.16 25.785 19.44 26.055 ;
     RECT  2.16 26.325 19.44 26.595 ;
     RECT  2.16 26.865 19.44 27.135 ;
     RECT  2.16 27.405 19.44 27.675 ;
     RECT  2.16 27.945 19.44 28.08 ;
    LAYER RVTP ;
     RECT  2.16 2.295 19.44 2.565 ;
     RECT  2.16 2.835 19.44 3.105 ;
     RECT  2.16 3.375 19.44 3.645 ;
     RECT  2.16 3.915 19.44 4.185 ;
     RECT  2.16 4.455 19.44 4.725 ;
     RECT  2.16 4.995 19.44 5.265 ;
     RECT  2.16 5.535 19.44 5.805 ;
     RECT  2.16 6.075 19.44 6.345 ;
     RECT  2.16 6.615 19.44 6.885 ;
     RECT  2.16 7.155 19.44 7.425 ;
     RECT  2.16 7.695 19.44 7.965 ;
     RECT  2.16 8.235 19.44 8.505 ;
     RECT  2.16 8.775 19.44 9.045 ;
     RECT  2.16 9.315 19.44 9.585 ;
     RECT  2.16 9.855 19.44 10.125 ;
     RECT  2.16 10.395 19.44 10.665 ;
     RECT  2.16 10.935 19.44 11.205 ;
     RECT  2.16 11.475 19.44 11.745 ;
     RECT  2.16 12.015 19.44 12.285 ;
     RECT  2.16 12.555 19.44 12.825 ;
     RECT  2.16 13.095 19.44 13.365 ;
     RECT  2.16 13.635 19.44 13.905 ;
     RECT  2.16 14.175 19.44 14.445 ;
     RECT  2.16 14.715 19.44 14.985 ;
     RECT  2.16 15.255 19.44 15.525 ;
     RECT  2.16 15.795 19.44 16.065 ;
     RECT  2.16 16.335 19.44 16.605 ;
     RECT  2.16 16.875 19.44 17.145 ;
     RECT  2.16 17.415 19.44 17.685 ;
     RECT  2.16 17.955 19.44 18.225 ;
     RECT  2.16 18.495 19.44 18.765 ;
     RECT  2.16 19.035 19.44 19.305 ;
     RECT  2.16 19.575 19.44 19.845 ;
     RECT  2.16 20.115 19.44 20.385 ;
     RECT  2.16 20.655 19.44 20.925 ;
     RECT  2.16 21.195 19.44 21.465 ;
     RECT  2.16 21.735 19.44 22.005 ;
     RECT  2.16 22.275 19.44 22.545 ;
     RECT  2.16 22.815 19.44 23.085 ;
     RECT  2.16 23.355 19.44 23.625 ;
     RECT  2.16 23.895 19.44 24.165 ;
     RECT  2.16 24.435 19.44 24.705 ;
     RECT  2.16 24.975 19.44 25.245 ;
     RECT  2.16 25.515 19.44 25.785 ;
     RECT  2.16 26.055 19.44 26.325 ;
     RECT  2.16 26.595 19.44 26.865 ;
     RECT  2.16 27.135 19.44 27.405 ;
     RECT  2.16 27.675 19.44 27.945 ;
    LAYER M1 ;
     RECT  2.16 2.151 19.44 28.089 ;
    LAYER M2 ;
     RECT  0.031 10.638 0.103 10.656 ;
     RECT  0.031 12.024 0.103 12.042 ;
     RECT  0.031 18.504 0.103 18.522 ;
     RECT  0.031 20.241 0.103 20.259 ;
     RECT  0.031 26.766 0.103 27.396 ;
     RECT  0.103 10.638 0.131 10.728 ;
     RECT  0.103 26.604 0.131 27.396 ;
     RECT  0.103 2.232 0.139 2.25 ;
     RECT  0.103 3.15 0.139 3.168 ;
     RECT  0.131 10.71 0.139 10.728 ;
     RECT  0.103 20.16 0.139 20.88 ;
     RECT  0.103 24.21 0.139 24.228 ;
     RECT  0.103 18 0.175 18.522 ;
     RECT  0.139 20.052 0.175 20.88 ;
     RECT  0.175 18 0.203 18.558 ;
     RECT  0.131 26.604 0.427 26.784 ;
     RECT  0.103 22.212 0.499 23.346 ;
     RECT  0.139 24.21 0.499 24.426 ;
     RECT  0.139 10.71 0.535 11.196 ;
     RECT  0.103 11.952 0.535 12.042 ;
     RECT  0.499 22.212 0.535 24.426 ;
     RECT  0.427 26.136 0.535 26.784 ;
     RECT  0.535 10.71 1.147 12.042 ;
     RECT  0.103 13.032 1.147 13.05 ;
     RECT  0.203 18.036 1.399 18.558 ;
     RECT  0.535 25.524 1.687 26.784 ;
     RECT  1.147 27.648 1.687 27.666 ;
     RECT  1.147 10.71 1.723 13.05 ;
     RECT  0.535 15.3 1.723 15.318 ;
     RECT  0.103 17.082 2.083 17.1 ;
     RECT  0.139 2.232 2.16 3.708 ;
     RECT  0.535 5.04 2.16 5.058 ;
     RECT  0.175 7.74 2.16 7.758 ;
     RECT  1.723 10.404 2.16 13.392 ;
     RECT  1.723 15.3 2.16 15.75 ;
     RECT  2.083 16.65 2.16 17.1 ;
     RECT  1.399 18.036 2.16 18.792 ;
     RECT  0.175 19.89 2.16 20.88 ;
     RECT  0.535 22.086 2.16 24.426 ;
     RECT  1.687 25.524 2.16 27.666 ;
     RECT  2.16 2.151 13.819 28.089 ;
     RECT  13.819 1.998 14.611 28.089 ;
     RECT  14.611 1.962 15.943 28.089 ;
     RECT  15.943 1.881 18.527 28.089 ;
     RECT  18.527 1.926 18.599 28.089 ;
     RECT  18.599 1.962 18.779 28.089 ;
     RECT  18.779 2.106 18.959 28.089 ;
     RECT  18.959 2.151 19.44 28.089 ;
     RECT  19.44 2.196 19.895 27.864 ;
     RECT  19.895 2.196 19.967 26.784 ;
     RECT  19.967 2.196 20.291 24.894 ;
     RECT  20.291 2.196 20.435 21.924 ;
     RECT  20.435 2.196 20.471 9.954 ;
     RECT  20.435 11.106 20.471 21.924 ;
     RECT  20.291 22.716 20.471 24.894 ;
     RECT  19.967 25.686 20.471 26.784 ;
     RECT  19.895 27.684 20.471 27.864 ;
     RECT  20.471 2.196 20.507 6.264 ;
     RECT  20.471 11.106 20.507 13.554 ;
     RECT  20.471 14.616 20.507 18.144 ;
     RECT  20.471 19.206 20.507 21.924 ;
     RECT  20.471 22.716 20.507 23.652 ;
     RECT  20.471 24.606 20.507 24.624 ;
     RECT  20.471 25.686 20.507 26.622 ;
     RECT  20.471 27.846 20.507 27.864 ;
     RECT  20.507 2.538 20.543 5.058 ;
     RECT  20.507 11.646 20.543 13.194 ;
     RECT  20.507 16.344 20.543 16.974 ;
     RECT  20.507 17.766 20.543 18.054 ;
     RECT  20.507 21.474 20.543 21.924 ;
     RECT  20.507 26.604 20.543 26.622 ;
     RECT  20.507 5.85 20.579 6.264 ;
     RECT  20.471 7.056 20.579 9.954 ;
     RECT  20.543 11.646 20.579 13.014 ;
     RECT  20.507 14.724 20.579 14.742 ;
     RECT  20.579 11.79 20.615 12.654 ;
     RECT  20.543 2.538 21.379 4.374 ;
     RECT  20.615 11.826 21.443 12.654 ;
     RECT  21.379 2.376 21.479 4.374 ;
     RECT  20.579 7.056 21.479 7.254 ;
     RECT  20.579 8.136 21.479 9.954 ;
     RECT  21.443 11.826 21.479 11.934 ;
     RECT  21.479 2.376 21.515 3.708 ;
     RECT  21.479 7.056 21.515 7.074 ;
     RECT  21.479 8.136 21.515 8.154 ;
     RECT  21.479 9.054 21.515 9.504 ;
     RECT  21.479 11.826 21.515 11.844 ;
     RECT  20.543 16.956 21.515 16.974 ;
     RECT  20.543 17.766 21.515 17.784 ;
     RECT  20.507 19.926 21.515 19.944 ;
     RECT  20.543 21.474 21.515 21.492 ;
     RECT  20.507 23.256 21.515 23.274 ;
     RECT  21.515 2.376 21.587 2.394 ;
     RECT  20.579 5.85 21.587 5.868 ;
    LAYER M3 ;
     RECT  18 0.715 18.018 0.811 ;
     RECT  21.348 1.003 21.366 1.099 ;
     RECT  19.836 0.907 19.854 1.291 ;
     RECT  19.836 1.291 20.502 1.483 ;
     RECT  19.656 1.483 20.502 1.771 ;
     RECT  15.948 1.876 15.966 1.921 ;
     RECT  18 0.811 18.558 1.921 ;
     RECT  19.296 1.771 20.502 1.921 ;
     RECT  18 1.921 20.502 1.993 ;
     RECT  15.948 1.921 16.398 2.029 ;
     RECT  17.568 1.993 20.502 2.029 ;
     RECT  14.616 1.957 14.634 2.065 ;
     RECT  15.588 2.029 20.502 2.065 ;
     RECT  13.824 1.993 13.842 2.143 ;
     RECT  2.415 2.143 2.505 2.191 ;
     RECT  13.215 2.143 13.842 2.191 ;
     RECT  14.616 2.065 20.502 2.191 ;
     RECT  13.215 2.191 20.502 2.263 ;
     RECT  12.528 2.263 20.502 2.335 ;
     RECT  21.348 1.099 21.51 2.371 ;
     RECT  7.815 2.143 7.905 2.413 ;
     RECT  2.415 2.191 2.754 2.461 ;
     RECT  0.108 2.227 0.126 2.497 ;
     RECT  12.276 2.335 20.502 2.533 ;
     RECT  2.415 2.461 2.826 2.569 ;
     RECT  5.94 2.533 5.958 2.731 ;
     RECT  6.84 2.461 6.858 2.731 ;
     RECT  7.815 2.413 8.097 2.767 ;
     RECT  11.304 2.569 11.322 2.767 ;
     RECT  21.348 2.371 21.582 2.831 ;
     RECT  5.94 2.731 6.858 2.839 ;
     RECT  7.74 2.767 8.097 2.839 ;
     RECT  9.504 2.371 9.522 2.839 ;
     RECT  11.232 2.767 11.322 2.839 ;
     RECT  5.94 2.839 8.097 2.869 ;
     RECT  8.82 2.839 9.522 2.869 ;
     RECT  5.94 2.869 9.522 2.875 ;
     RECT  10.584 2.839 11.322 2.875 ;
     RECT  0.108 2.497 0.27 2.911 ;
     RECT  5.94 2.875 11.43 2.911 ;
     RECT  12.204 2.533 20.502 2.911 ;
     RECT  2.415 2.569 3.078 3.001 ;
     RECT  2.415 3.001 3.258 3.145 ;
     RECT  4.608 3.109 4.626 3.271 ;
     RECT  5.94 2.911 20.502 3.271 ;
     RECT  2.376 3.145 3.258 3.307 ;
     RECT  2.304 3.307 3.258 3.344 ;
     RECT  2.34 3.344 3.258 3.379 ;
     RECT  4.608 3.271 20.502 3.415 ;
     RECT  2.34 3.379 3.546 3.451 ;
     RECT  4.392 3.415 20.502 3.451 ;
     RECT  0.108 2.911 0.342 3.725 ;
     RECT  0.108 3.725 0.306 3.821 ;
     RECT  0.108 3.821 0.198 4.109 ;
     RECT  2.34 3.451 20.502 4.171 ;
     RECT  21.42 2.831 21.582 4.267 ;
     RECT  0.108 4.109 0.162 4.301 ;
     RECT  21.384 4.267 21.582 4.541 ;
     RECT  0.144 4.301 0.162 4.973 ;
     RECT  2.304 4.171 20.502 5.029 ;
     RECT  2.304 5.029 20.538 5.069 ;
     RECT  2.304 5.069 20.502 5.323 ;
     RECT  2.268 5.323 20.502 5.419 ;
     RECT  2.232 5.419 20.502 5.495 ;
     RECT  0.54 5.035 0.558 5.645 ;
     RECT  0.324 5.707 0.342 5.803 ;
     RECT  21.564 4.541 21.582 5.873 ;
     RECT  0.216 5.803 0.342 5.981 ;
     RECT  2.268 5.495 20.502 5.981 ;
     RECT  21.312 5.899 21.51 6.029 ;
     RECT  0.324 5.981 0.342 6.125 ;
     RECT  2.304 5.981 20.502 6.187 ;
     RECT  2.304 6.187 20.574 6.269 ;
     RECT  2.304 6.269 20.538 6.509 ;
     RECT  19.872 6.509 20.538 6.719 ;
     RECT  21.492 6.029 21.51 6.763 ;
     RECT  21.456 6.763 21.51 6.859 ;
     RECT  2.304 6.509 19.134 7.051 ;
     RECT  21.42 6.859 21.51 7.051 ;
     RECT  2.268 7.051 19.134 7.357 ;
     RECT  2.268 7.357 19.206 7.385 ;
     RECT  19.944 6.719 20.538 7.435 ;
     RECT  8.892 7.385 19.206 7.501 ;
     RECT  19.944 7.435 20.574 7.501 ;
     RECT  1.404 7.339 1.422 7.627 ;
     RECT  2.268 7.385 8.097 7.627 ;
     RECT  0.216 7.531 0.234 7.709 ;
     RECT  8.892 7.501 20.574 7.799 ;
     RECT  8.892 7.799 20.538 7.961 ;
     RECT  1.404 7.627 8.097 8.131 ;
     RECT  8.892 7.961 9.594 8.131 ;
     RECT  0.18 7.735 0.198 8.237 ;
     RECT  0.324 8.683 0.342 8.813 ;
     RECT  1.404 8.131 9.594 8.815 ;
     RECT  10.332 7.961 20.538 8.815 ;
     RECT  21.384 7.051 21.51 9.239 ;
     RECT  1.404 8.815 20.538 9.319 ;
     RECT  1.404 9.319 20.574 9.389 ;
     RECT  1.404 9.389 20.538 9.419 ;
     RECT  21.456 9.239 21.51 9.959 ;
     RECT  1.404 9.419 20.502 10.027 ;
     RECT  1.152 10.027 20.502 10.427 ;
     RECT  0.108 9.931 0.126 10.633 ;
     RECT  1.152 10.427 1.422 10.931 ;
     RECT  2.304 10.427 20.502 11.083 ;
     RECT  0.036 10.633 0.126 11.173 ;
     RECT  2.304 11.083 20.538 11.213 ;
     RECT  21.492 9.959 21.51 11.275 ;
     RECT  2.304 11.213 18.99 11.281 ;
     RECT  19.908 11.213 20.538 11.309 ;
     RECT  20.196 11.309 20.538 11.641 ;
     RECT  0.036 11.173 0.162 11.713 ;
     RECT  1.152 10.931 1.17 11.713 ;
     RECT  21.456 11.275 21.51 11.755 ;
     RECT  20.196 11.641 20.574 11.785 ;
     RECT  21.42 11.755 21.51 11.849 ;
     RECT  20.196 11.785 20.61 11.885 ;
     RECT  21.42 11.849 21.474 11.939 ;
     RECT  2.268 11.281 18.99 11.947 ;
     RECT  0.036 11.713 1.17 12.019 ;
     RECT  2.124 11.947 19.314 12.019 ;
     RECT  0.036 12.019 19.314 12.047 ;
     RECT  20.196 11.885 20.574 12.077 ;
     RECT  20.196 12.077 20.538 12.173 ;
     RECT  0.108 12.047 19.314 12.269 ;
     RECT  0.144 12.269 19.314 12.289 ;
     RECT  20.196 12.173 20.502 12.289 ;
     RECT  0.144 12.289 20.502 12.365 ;
     RECT  1.152 12.365 20.502 12.389 ;
     RECT  21.42 11.939 21.438 12.659 ;
     RECT  1.728 12.389 20.502 12.991 ;
     RECT  0.144 12.365 0.162 13.027 ;
     RECT  0.108 13.027 0.162 13.325 ;
     RECT  1.728 12.991 20.574 13.397 ;
     RECT  0.324 13.483 0.342 13.613 ;
     RECT  2.268 13.397 20.574 13.613 ;
     RECT  2.268 13.613 20.502 14.155 ;
     RECT  1.728 14.155 20.502 14.719 ;
     RECT  1.728 14.719 20.574 14.765 ;
     RECT  0.216 14.923 0.234 15.115 ;
     RECT  0.216 15.115 0.342 15.293 ;
     RECT  0.54 15.295 0.558 15.437 ;
     RECT  1.728 14.765 20.502 15.629 ;
     RECT  1.728 15.629 19.026 15.755 ;
     RECT  2.088 15.755 19.026 16.025 ;
     RECT  19.908 15.629 20.502 16.339 ;
     RECT  19.908 16.339 20.538 16.397 ;
     RECT  19.908 16.397 20.502 16.555 ;
     RECT  2.088 16.025 18.99 16.673 ;
     RECT  0.324 16.171 0.342 16.877 ;
     RECT  2.268 16.673 18.99 16.915 ;
     RECT  19.872 16.555 20.502 16.915 ;
     RECT  2.268 16.915 20.502 17.411 ;
     RECT  21.492 16.267 21.51 17.789 ;
     RECT  0.108 17.077 0.126 17.803 ;
     RECT  0.108 17.803 0.162 17.98 ;
     RECT  0.108 17.98 0.198 18.031 ;
     RECT  2.304 17.411 20.502 18.031 ;
     RECT  0.108 18.031 0.558 18.413 ;
     RECT  0.108 18.413 0.342 18.499 ;
     RECT  2.304 18.031 20.538 18.605 ;
     RECT  2.304 18.605 20.502 19.139 ;
     RECT  20.268 19.139 20.502 19.229 ;
     RECT  20.268 19.229 20.466 19.337 ;
     RECT  20.268 19.337 20.286 19.373 ;
     RECT  2.304 19.139 19.422 19.915 ;
     RECT  2.304 19.915 19.926 19.963 ;
     RECT  0.036 18.499 0.342 20.005 ;
     RECT  0.036 20.005 0.45 20.011 ;
     RECT  1.404 18.769 1.422 20.011 ;
     RECT  0.036 20.011 1.422 20.045 ;
     RECT  2.268 19.963 19.926 20.045 ;
     RECT  19.872 20.045 19.926 20.107 ;
     RECT  0.036 20.045 0.342 20.141 ;
     RECT  2.268 20.045 18.99 20.203 ;
     RECT  21.492 19.921 21.51 20.237 ;
     RECT  0.036 20.141 0.234 20.264 ;
     RECT  0.108 20.264 0.234 20.525 ;
     RECT  2.232 20.203 18.99 21.091 ;
     RECT  19.872 20.107 20.502 21.091 ;
     RECT  1.152 20.045 1.422 21.197 ;
     RECT  0.108 20.525 0.198 21.293 ;
     RECT  21.492 21.355 21.51 21.497 ;
     RECT  2.232 21.091 20.502 21.803 ;
     RECT  2.268 21.803 20.502 21.901 ;
     RECT  0.108 21.293 0.162 22.081 ;
     RECT  1.152 21.197 1.17 22.081 ;
     RECT  2.268 21.901 20.538 22.253 ;
     RECT  0.108 22.081 1.17 22.379 ;
     RECT  21.42 22.267 21.438 22.445 ;
     RECT  0.108 22.379 0.558 22.541 ;
     RECT  2.268 22.253 20.502 22.649 ;
     RECT  21.492 23.251 21.51 23.405 ;
     RECT  0.108 22.541 0.342 23.629 ;
     RECT  2.304 22.649 20.502 23.701 ;
     RECT  2.268 23.701 20.502 24.503 ;
     RECT  0.108 23.629 0.558 24.557 ;
     RECT  0.144 24.557 0.558 24.749 ;
     RECT  2.304 24.503 20.502 25.229 ;
     RECT  2.304 25.229 6.858 25.753 ;
     RECT  2.268 25.753 6.858 25.901 ;
     RECT  0.54 24.749 0.558 26.131 ;
     RECT  2.304 25.901 6.858 26.251 ;
     RECT  7.815 25.229 20.502 26.251 ;
     RECT  0.432 26.131 0.558 26.477 ;
     RECT  2.304 26.251 20.502 26.599 ;
     RECT  0.108 26.599 0.126 26.761 ;
     RECT  1.152 26.635 1.17 26.789 ;
     RECT  2.304 26.599 20.538 26.957 ;
     RECT  2.304 26.957 20.502 26.969 ;
     RECT  2.304 26.969 19.386 27.059 ;
     RECT  2.304 27.059 8.982 27.103 ;
     RECT  1.692 27.103 8.982 27.167 ;
     RECT  1.692 27.167 8.154 27.203 ;
     RECT  8.928 27.167 8.982 27.203 ;
     RECT  9.828 27.059 19.35 27.239 ;
     RECT  8.928 27.203 8.946 27.329 ;
     RECT  9.828 27.239 19.17 27.329 ;
     RECT  0.036 26.761 0.126 27.401 ;
     RECT  9.828 27.329 12.114 27.599 ;
     RECT  13.215 27.329 19.17 27.599 ;
     RECT  1.692 27.203 8.097 27.635 ;
     RECT  9.828 27.599 10.926 27.635 ;
     RECT  1.692 27.635 6.102 27.643 ;
     RECT  13.215 27.599 19.026 27.671 ;
     RECT  7.128 27.635 8.097 27.707 ;
     RECT  9.828 27.635 10.674 27.707 ;
     RECT  20.448 26.969 20.502 27.707 ;
     RECT  7.416 27.707 8.097 27.743 ;
     RECT  9.828 27.707 10.566 27.743 ;
     RECT  13.215 27.671 16.326 27.779 ;
     RECT  7.815 27.743 8.097 27.827 ;
     RECT  9.864 27.743 9.882 27.869 ;
     RECT  12.096 27.599 12.114 27.869 ;
     RECT  13.215 27.779 15.642 27.869 ;
     RECT  17.064 27.671 19.026 27.869 ;
     RECT  20.484 27.707 20.502 27.869 ;
     RECT  1.152 27.643 6.102 27.905 ;
     RECT  17.136 27.869 19.026 27.905 ;
     RECT  5.508 27.905 6.102 27.941 ;
     RECT  13.215 27.869 14.526 27.941 ;
     RECT  15.264 27.869 15.282 27.941 ;
     RECT  17.136 27.905 17.766 27.941 ;
     RECT  17.748 27.941 17.766 28.049 ;
     RECT  1.152 27.905 3.402 28.097 ;
     RECT  7.815 27.827 7.905 28.097 ;
     RECT  13.215 27.941 13.305 28.097 ;
     RECT  18.615 27.905 18.705 28.097 ;
     RECT  0.108 27.401 0.126 28.205 ;
     RECT  2.664 28.097 3.402 28.301 ;
     RECT  2.664 28.301 3.294 28.397 ;
     RECT  2.736 28.397 3.294 28.493 ;
     RECT  2.736 28.493 2.754 29.069 ;
     RECT  14.508 27.941 14.526 29.117 ;
     RECT  1.152 28.097 1.71 29.261 ;
     RECT  1.152 29.261 1.17 29.357 ;
    LAYER M4 ;
     RECT  0.06 3.216 0.097 29.448 ;
     RECT  0.097 3.072 0.209 29.448 ;
     RECT  0.209 3.312 0.275 29.448 ;
     RECT  0.275 11.088 0.371 29.448 ;
     RECT  0.275 3.312 1.181 10.056 ;
     RECT  0.371 11.088 1.181 29.352 ;
     RECT  1.181 11.088 1.721 29.256 ;
     RECT  1.181 3.312 2.408 9.864 ;
     RECT  1.721 11.088 2.408 29.064 ;
     RECT  2.408 2.148 2.512 29.064 ;
     RECT  2.512 2.418 2.704 29.064 ;
     RECT  2.704 3.744 2.765 29.064 ;
     RECT  2.765 3.744 2.981 28.488 ;
     RECT  2.981 3.744 3.017 23.4 ;
     RECT  3.017 3.744 3.053 23.352 ;
     RECT  2.981 24.48 3.305 28.488 ;
     RECT  3.305 24.48 3.413 28.296 ;
     RECT  3.413 24.48 3.449 27.72 ;
     RECT  3.449 24.48 3.737 27.672 ;
     RECT  3.053 3.744 3.949 7.896 ;
     RECT  3.053 9.024 4.061 23.352 ;
     RECT  3.949 3.648 4.309 7.896 ;
     RECT  4.061 9.024 4.309 23.208 ;
     RECT  3.737 24.96 4.313 27.672 ;
     RECT  4.309 3.648 4.673 23.208 ;
     RECT  4.673 4.656 4.781 23.208 ;
     RECT  4.313 24.96 4.817 25.128 ;
     RECT  4.313 26.16 4.885 27.672 ;
     RECT  4.885 26.16 4.961 27.72 ;
     RECT  4.781 8.688 5.125 23.208 ;
     RECT  5.125 8.688 5.137 23.352 ;
     RECT  4.849 24.528 5.137 24.552 ;
     RECT  5.137 8.688 5.321 24.552 ;
     RECT  4.673 3.648 5.533 3.672 ;
     RECT  5.533 3.6 5.641 3.672 ;
     RECT  4.781 4.656 5.825 7.704 ;
     RECT  5.321 8.688 6.001 22.008 ;
     RECT  4.961 26.256 6.077 27.72 ;
     RECT  5.321 23.136 6.109 24.552 ;
     RECT  6.001 8.496 6.289 22.008 ;
     RECT  6.109 23.136 6.289 25.224 ;
     RECT  6.289 8.496 6.365 25.224 ;
     RECT  5.641 3.408 6.469 3.672 ;
     RECT  5.825 4.656 6.469 7.272 ;
     RECT  6.469 3.408 6.473 7.272 ;
     RECT  6.473 3.408 6.541 6.84 ;
     RECT  6.365 11.52 6.545 25.224 ;
     RECT  6.545 11.52 6.761 23.64 ;
     RECT  6.365 8.496 7.405 10.296 ;
     RECT  6.761 11.52 7.405 13.704 ;
     RECT  7.405 8.496 7.585 13.704 ;
     RECT  6.541 3.072 7.808 6.84 ;
     RECT  7.585 8.16 7.808 13.704 ;
     RECT  6.761 14.832 7.808 23.64 ;
     RECT  6.545 25.2 7.808 25.224 ;
     RECT  6.077 26.256 7.808 27.144 ;
     RECT  7.808 2.148 7.912 28.092 ;
     RECT  7.912 2.418 8.104 27.822 ;
     RECT  8.104 14.928 8.201 24.552 ;
     RECT  8.104 2.88 8.531 13.704 ;
     RECT  8.104 25.536 8.669 27.144 ;
     RECT  8.531 2.88 8.921 6.84 ;
     RECT  8.201 15.264 9.205 24.552 ;
     RECT  9.205 15.168 9.245 24.552 ;
     RECT  8.531 7.872 9.317 13.704 ;
     RECT  9.245 18.672 9.349 24.552 ;
     RECT  8.669 25.536 9.349 26.76 ;
     RECT  9.317 7.872 9.497 12.264 ;
     RECT  9.245 15.168 9.601 17.352 ;
     RECT  9.601 15.024 9.637 17.352 ;
     RECT  9.349 18.672 9.713 26.76 ;
     RECT  8.921 3.408 9.997 6.84 ;
     RECT  9.713 21.12 10.145 26.76 ;
     RECT  9.497 9.792 10.285 12.264 ;
     RECT  9.997 3.024 10.465 6.84 ;
     RECT  10.145 21.12 10.541 26.712 ;
     RECT  9.637 14.016 10.645 17.352 ;
     RECT  9.713 18.672 10.645 19.944 ;
     RECT  10.285 9.792 10.685 12.552 ;
     RECT  10.645 14.016 10.685 19.944 ;
     RECT  10.465 2.88 10.825 6.84 ;
     RECT  9.497 7.872 10.825 8.712 ;
     RECT  10.685 14.016 10.837 18.264 ;
     RECT  10.541 25.536 10.937 26.712 ;
     RECT  10.685 9.84 11.149 12.552 ;
     RECT  10.837 13.68 11.149 18.264 ;
     RECT  10.937 26.256 11.149 26.712 ;
     RECT  10.685 19.248 11.513 19.944 ;
     RECT  10.541 21.12 11.765 24.552 ;
     RECT  11.765 23.376 11.837 24.552 ;
     RECT  10.825 2.88 11.869 8.712 ;
     RECT  11.149 9.84 11.869 18.264 ;
     RECT  11.513 19.248 11.869 19.56 ;
     RECT  11.869 2.88 11.909 19.56 ;
     RECT  11.837 23.376 11.945 23.784 ;
     RECT  11.149 26.256 11.977 26.76 ;
     RECT  11.977 26.256 12.013 26.856 ;
     RECT  11.909 2.88 12.661 19.512 ;
     RECT  11.765 21.12 13.093 22.008 ;
     RECT  11.945 23.376 13.165 23.4 ;
     RECT  12.013 26.208 13.165 26.856 ;
     RECT  12.661 2.592 13.208 19.512 ;
     RECT  13.093 20.688 13.208 22.008 ;
     RECT  13.165 23.376 13.208 23.64 ;
     RECT  13.165 25.776 13.208 26.856 ;
     RECT  13.208 2.148 13.312 28.092 ;
     RECT  13.312 2.418 13.504 27.822 ;
     RECT  13.504 2.544 13.745 8.616 ;
     RECT  13.745 2.544 13.889 8.568 ;
     RECT  13.504 22.944 13.907 27.72 ;
     RECT  13.907 22.944 14.033 26.856 ;
     RECT  13.504 10.032 14.465 21.96 ;
     RECT  13.889 2.544 14.537 8.52 ;
     RECT  14.537 2.544 14.677 8.472 ;
     RECT  14.033 22.944 14.789 26.712 ;
     RECT  14.677 2.208 14.861 8.472 ;
     RECT  14.497 29.088 14.867 29.112 ;
     RECT  14.465 10.032 14.897 21.864 ;
     RECT  14.897 10.032 15.041 13.032 ;
     RECT  15.041 10.032 15.077 10.392 ;
     RECT  14.897 14.64 15.149 21.864 ;
     RECT  15.149 17.856 15.185 21.864 ;
     RECT  15.185 18 15.221 21.864 ;
     RECT  15.221 20.88 15.257 21.864 ;
     RECT  15.041 11.376 15.329 13.032 ;
     RECT  15.077 10.032 15.401 10.344 ;
     RECT  15.149 14.64 15.437 16.296 ;
     RECT  15.257 21.168 15.437 21.864 ;
     RECT  14.789 23.376 15.437 26.664 ;
     RECT  15.329 11.376 15.509 12.6 ;
     RECT  15.437 23.376 15.833 25.032 ;
     RECT  15.221 18 15.869 19.608 ;
     RECT  14.861 2.208 15.901 8.184 ;
     RECT  15.757 9.744 15.901 9.768 ;
     RECT  15.509 11.376 16.117 12.504 ;
     RECT  15.437 26.4 16.153 26.664 ;
     RECT  15.869 19.2 16.441 19.608 ;
     RECT  15.437 21.168 16.441 21.192 ;
     RECT  15.833 24.864 16.441 25.032 ;
     RECT  16.153 26.4 16.441 26.76 ;
     RECT  15.973 13.584 16.477 13.608 ;
     RECT  15.869 18 16.477 18.024 ;
     RECT  16.441 19.2 16.553 21.192 ;
     RECT  16.441 24.864 16.553 26.76 ;
     RECT  16.477 17.04 16.585 18.024 ;
     RECT  15.901 2.208 16.693 9.768 ;
     RECT  16.117 11.136 16.693 12.504 ;
     RECT  16.477 13.536 16.693 13.608 ;
     RECT  15.437 14.64 16.693 15.72 ;
     RECT  16.585 16.944 16.697 18.024 ;
     RECT  15.833 23.376 16.841 23.4 ;
     RECT  16.553 24.864 17.057 26.52 ;
     RECT  16.697 17.04 17.125 18.024 ;
     RECT  16.553 19.2 17.125 20.376 ;
     RECT  17.125 17.04 17.201 20.376 ;
     RECT  16.693 2.208 17.305 12.504 ;
     RECT  16.693 13.536 17.305 15.72 ;
     RECT  17.305 2.208 17.597 15.72 ;
     RECT  17.557 22.224 17.629 22.248 ;
     RECT  17.377 23.664 17.665 23.688 ;
     RECT  17.057 24.864 17.665 26.424 ;
     RECT  17.629 22.224 17.809 22.536 ;
     RECT  17.809 22.08 18.133 22.536 ;
     RECT  17.201 17.04 18.421 19.224 ;
     RECT  17.989 0.72 18.529 0.744 ;
     RECT  17.597 2.208 18.608 9.528 ;
     RECT  17.597 10.848 18.608 15.72 ;
     RECT  18.421 16.8 18.608 19.224 ;
     RECT  17.201 20.304 18.608 20.376 ;
     RECT  18.133 22.032 18.608 22.536 ;
     RECT  17.665 23.664 18.608 26.424 ;
     RECT  18.608 2.148 18.712 28.092 ;
     RECT  18.712 2.148 18.904 27.822 ;
     RECT  18.904 2.148 18.997 15.528 ;
     RECT  18.904 16.56 19.037 27.096 ;
     RECT  18.529 0.72 19.285 0.84 ;
     RECT  18.997 2.064 19.285 15.528 ;
     RECT  19.285 0.72 19.897 15.528 ;
     RECT  19.037 16.56 19.897 26.568 ;
     RECT  19.897 0.72 20.437 26.568 ;
     RECT  20.437 0.72 20.509 26.856 ;
     RECT  20.509 0.72 21.564 26.952 ;
    LAYER M5 ;
     RECT  2.4 2.137 2.52 2.151 ;
     RECT  7.8 2.137 7.92 2.151 ;
     RECT  13.2 2.137 13.32 2.151 ;
     RECT  18.6 2.137 18.72 2.151 ;
     RECT  13.2 2.151 13.512 2.581 ;
     RECT  12.672 2.581 13.512 2.915 ;
     RECT  7.8 2.151 8.112 3.925 ;
     RECT  6.48 3.397 6.504 3.971 ;
     RECT  7.68 3.925 8.112 4.837 ;
     RECT  7.68 4.837 8.568 5.171 ;
     RECT  7.8 5.171 8.568 5.219 ;
     RECT  2.4 2.151 2.712 5.845 ;
     RECT  3.888 5.317 3.912 5.845 ;
     RECT  21.408 5.989 21.432 6.179 ;
     RECT  0.192 6.085 0.216 6.275 ;
     RECT  7.8 5.219 8.112 6.661 ;
     RECT  0.24 6.469 0.264 7.237 ;
     RECT  0.144 7.237 0.264 7.523 ;
     RECT  0.24 7.523 0.264 8.195 ;
     RECT  7.8 6.661 8.52 8.195 ;
     RECT  6.192 5.365 6.216 8.485 ;
     RECT  0.144 8.773 0.168 9.059 ;
     RECT  6.192 8.485 6.792 9.155 ;
     RECT  6.192 9.155 6.216 9.635 ;
     RECT  2.4 5.845 3.912 10.067 ;
     RECT  7.8 8.195 8.112 10.069 ;
     RECT  0.144 10.117 0.168 10.213 ;
     RECT  7.8 10.069 9.096 10.501 ;
     RECT  7.8 10.501 9.384 10.597 ;
     RECT  12 9.397 12.024 11.027 ;
     RECT  10.896 10.789 10.92 11.459 ;
     RECT  2.4 10.067 2.712 11.845 ;
     RECT  7.8 10.597 9.48 11.987 ;
     RECT  0.144 10.213 0.264 12.611 ;
     RECT  2.4 11.845 2.856 12.853 ;
     RECT  2.304 12.853 2.856 13.045 ;
     RECT  3.888 10.067 3.912 13.045 ;
     RECT  13.2 2.915 13.512 13.141 ;
     RECT  0.144 12.611 0.168 13.619 ;
     RECT  13.008 13.141 13.512 13.667 ;
     RECT  10.848 12.517 10.872 13.715 ;
     RECT  2.304 13.045 3.912 13.861 ;
     RECT  2.304 13.861 4.584 14.339 ;
     RECT  2.4 14.339 4.584 14.771 ;
     RECT  0.144 14.965 0.168 15.251 ;
     RECT  13.2 13.667 13.512 15.301 ;
     RECT  2.4 14.771 3.912 15.443 ;
     RECT  6.144 9.685 6.168 15.443 ;
     RECT  13.2 15.301 13.704 16.019 ;
     RECT  2.4 15.443 2.808 16.693 ;
     RECT  0.144 16.309 0.168 16.883 ;
     RECT  3.888 15.443 3.912 17.077 ;
     RECT  2.4 16.693 2.856 17.219 ;
     RECT  2.4 17.219 2.808 17.411 ;
     RECT  3.888 17.077 4.824 17.605 ;
     RECT  13.2 16.019 13.512 18.181 ;
     RECT  14.736 15.493 14.76 18.181 ;
     RECT  11.184 15.349 11.208 18.229 ;
     RECT  7.8 11.987 8.112 18.709 ;
     RECT  3.792 17.605 4.824 18.995 ;
     RECT  9.36 11.987 9.384 19.427 ;
     RECT  11.136 18.229 11.208 19.427 ;
     RECT  11.184 19.427 11.208 19.523 ;
     RECT  13.2 18.181 14.76 19.763 ;
     RECT  7.68 18.709 8.112 19.811 ;
     RECT  0.144 19.093 0.168 19.861 ;
     RECT  0.144 19.861 0.264 20.003 ;
     RECT  3.792 18.995 4.056 20.101 ;
     RECT  3.792 20.101 4.68 20.291 ;
     RECT  0.24 20.003 0.264 20.339 ;
     RECT  3.792 20.291 4.44 20.485 ;
     RECT  5.712 19.861 5.736 20.579 ;
     RECT  2.4 17.411 2.712 20.629 ;
     RECT  3.744 20.485 4.44 20.629 ;
     RECT  7.8 19.811 8.112 21.013 ;
     RECT  2.4 20.629 4.44 21.155 ;
     RECT  3.888 21.155 4.44 21.203 ;
     RECT  13.2 19.763 13.512 21.781 ;
     RECT  2.4 21.155 2.856 21.827 ;
     RECT  7.8 21.013 8.232 21.829 ;
     RECT  13.2 21.781 13.608 22.979 ;
     RECT  11.376 22.165 11.4 23.411 ;
     RECT  7.8 21.829 8.472 23.605 ;
     RECT  5.136 21.253 5.16 24.563 ;
     RECT  7.8 23.605 8.52 24.563 ;
     RECT  10.272 23.893 10.296 24.659 ;
     RECT  0.288 24.469 0.312 24.949 ;
     RECT  3.888 21.203 4.056 25.187 ;
     RECT  0.144 24.949 0.312 25.237 ;
     RECT  2.4 21.827 2.712 25.429 ;
     RECT  7.8 24.563 8.472 25.763 ;
     RECT  2.4 25.429 2.856 25.957 ;
     RECT  4.032 25.187 4.056 26.243 ;
     RECT  10.272 25.621 10.296 26.291 ;
     RECT  2.4 25.957 3.048 26.819 ;
     RECT  13.2 22.979 13.512 26.821 ;
     RECT  14.736 19.763 14.76 26.821 ;
     RECT  0.144 25.237 0.552 27.061 ;
     RECT  0.144 27.061 0.648 27.205 ;
     RECT  2.4 26.819 2.856 27.683 ;
     RECT  13.2 26.821 14.76 27.731 ;
     RECT  0.144 27.205 0.696 28.019 ;
     RECT  2.4 27.683 2.712 28.089 ;
     RECT  7.8 25.763 8.112 28.089 ;
     RECT  13.2 27.731 13.512 28.089 ;
     RECT  18.6 2.151 18.912 28.089 ;
     RECT  2.4 28.089 2.52 28.103 ;
     RECT  7.8 28.089 7.92 28.103 ;
     RECT  13.2 28.089 13.32 28.103 ;
     RECT  18.6 28.089 18.72 28.103 ;
     RECT  0.288 28.019 0.696 28.883 ;
     RECT  0.288 28.883 0.552 28.979 ;
     RECT  14.736 27.731 14.76 29.077 ;
     RECT  0.288 28.979 0.36 29.171 ;
     RECT  0.336 29.171 0.36 29.459 ;
     RECT  14.736 29.077 14.856 30.224 ;
  END
END dsfd_rly_266_WE
END LIBRARY
